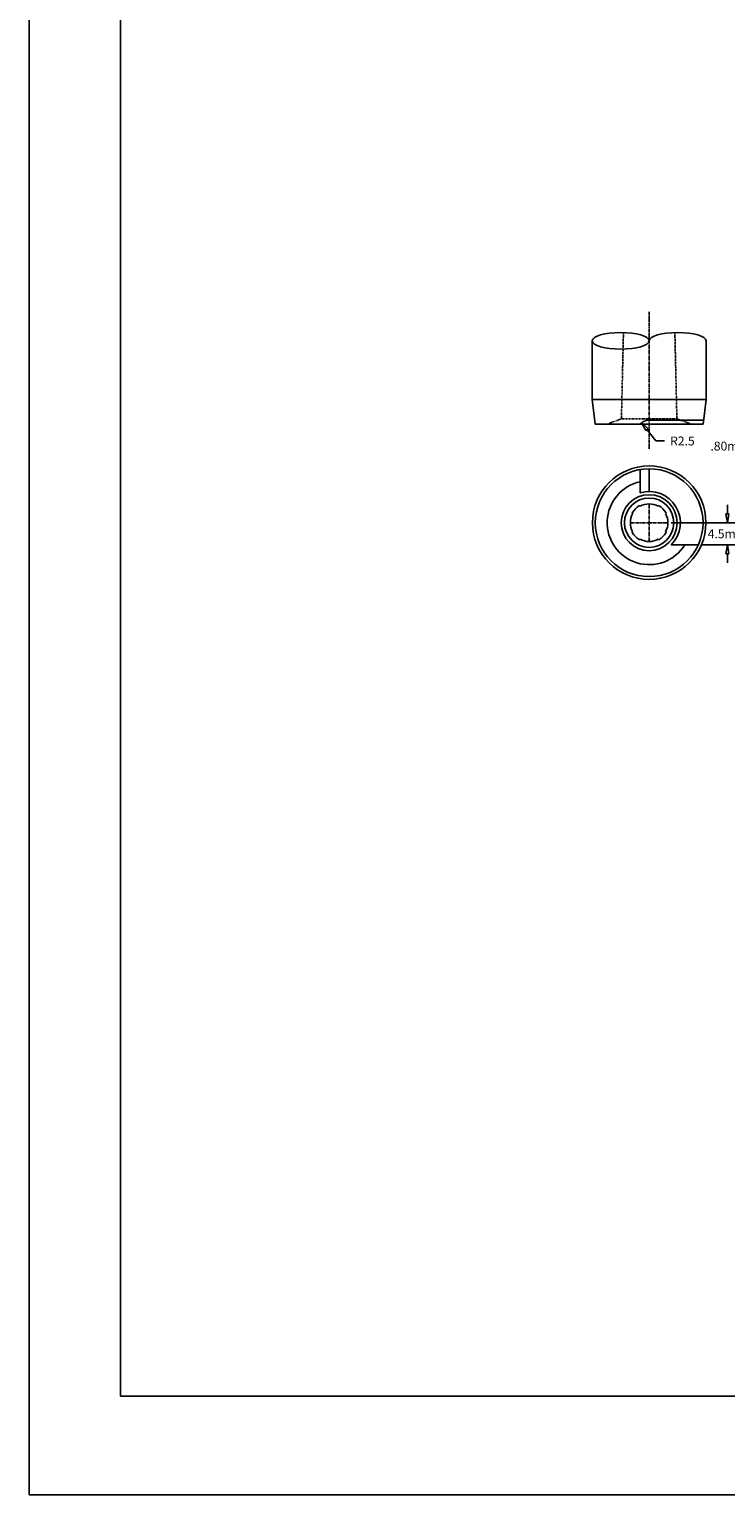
# Model space of a CAD drawing. Units: inches. Extents: x 0 to 841, y 0 to 594.
# Drawn here: x 0 to 141, y 0 to 297 of the extents above; entities that cross this region are included whole.
import ezdxf

# ---------------------------------------------------------------- set-up
doc = ezdxf.new("R2010")
doc.units = ezdxf.units.IN
doc.header["$MEASUREMENT"] = 0
doc.linetypes.add('CENTER2', pattern=[1.125, 0.75, -0.125, 0.125, -0.125])
doc.linetypes.add('HIDDEN2', pattern=[0.1875, 0.125, -0.0625])
doc.layers.add('CENTERLINE', color=1, linetype='CENTER2')
doc.layers.add('HIDDEN', color=5, linetype='HIDDEN2')
doc.dimstyles.get("Standard").update_dxf_attribs({"dimscale": 10, "dimtxt": 0.18, "dimasz": 0.18, "dimexe": 0.18, "dimexo": 0.0625, "dimgap": 0.09, "dimtad": 0, "dimtih": 1, "dimtoh": 1, "dimdec": 4, "dimzin": 0, "dimdsep": 46, "dimtxsty": 'Standard', "dimblk": 'CLOSEDBLANK', "dimcen": 0.09, "dimadec": 4, "dimazin": 0, "dimtfac": 1, "dimtdec": 4, "dimtofl": 0, "dimtmove": 0, "dimatfit": 3, "dimldrblk": 'CLOSEDBLANK', "dimfxl": 0, "dimtolj": 1, "dimtzin": 0, "dimarcsym": 0})
doc.dimstyles.new('Standard$0', dxfattribs={"dimscale": 10, "dimtxt": 0.18, "dimasz": 0.18, "dimexe": 0.18, "dimexo": 0.0625, "dimgap": 0.09, "dimtad": 0, "dimtih": 1, "dimtoh": 1, "dimdec": 4, "dimzin": 4, "dimdsep": 46, "dimtxsty": 'Standard', "dimblk": 'CLOSEDBLANK', "dimcen": 0.09, "dimadec": 5, "dimazin": 1, "dimtfac": 1, "dimtdec": 4, "dimtofl": 0, "dimtmove": 0, "dimatfit": 3, "dimldrblk": 'CLOSEDBLANK', "dimfxl": 0, "dimtolj": 1, "dimtzin": 0, "dimarcsym": 0})

# ---------------------------------------------------------------- blocks, each defined once
blk = doc.blocks.new('_ClosedBlank')
at = {"color": 0, "linetype": 'ByBlock', "lineweight": -2}
for p, q in [((-1, 0.17), (0, 0)), ((-1, 0.17), (-1, -0.17)), ((0, 0), (-1, -0.17))]:
    blk.add_line(p, q, dxfattribs=at)
blk = doc.blocks.new('*D7')
at = {"color": 0, "lineweight": -2}
for p, q in [((150, 208.55), (150, 214.33)), ((150.8, 208.43), (150.8, 214.33)), ((148.2, 212.53), (146.4, 212.53)), ((152.6, 212.53), (154.4, 212.53))]:
    blk.add_line(p, q, dxfattribs=at)
at = {"layer": 'Defpoints', "color": 0}
for p in [(150.8, 212.53), (150, 207.92), (150.8, 207.8)]:
    blk.add_point(p, dxfattribs=at)
at = {"color": 0, "lineweight": -2, "xscale": 1.8, "yscale": 1.8, "zscale": 1.8}
blk.add_blockref('_ClosedBlank', (150, 212.53), dxfattribs=at)
at = {"color": 0, "lineweight": -2, "xscale": 1.8, "yscale": 1.8, "zscale": 1.8, "rotation": 180}
blk.add_blockref('_ClosedBlank', (150.8, 212.53), dxfattribs=at)
at = {"color": 0, "insert": (142.05, 212.53), "char_height": 1.8, "attachment_point": 5}
blk.add_mtext('\\A1;.80mm', dxfattribs=at)
blk = doc.blocks.new('*D24')
at = {"color": 0, "lineweight": -2}
for p, q in [((141.5, 198.8), (141.5, 200.6)), ((130.08, 197), (143.3, 197)), ((136.23, 192.5), (143.3, 192.5)), ((141.5, 190.7), (141.5, 188.9))]:
    blk.add_line(p, q, dxfattribs=at)
at = {"layer": 'Defpoints', "color": 0}
for p in [(129.46, 197), (141.5, 197), (135.6, 192.5)]:
    blk.add_point(p, dxfattribs=at)
at = {"color": 0, "lineweight": -2, "xscale": 1.8, "yscale": 1.8, "zscale": 1.8}
for p, rotation in [((141.5, 197), 270), ((141.5, 192.5), 90)]:
    blk.add_blockref('_ClosedBlank', p, dxfattribs=dict(at, rotation=rotation))
at = {"color": 0, "insert": (141.5, 194.75), "char_height": 1.8, "attachment_point": 5}
blk.add_mtext('\\A1;4.5mm', dxfattribs=at)
blk = doc.blocks.new('*D25')
at = {"color": 0, "lineweight": -2}
for p, q in [((126.99, 213.56), (125.22, 215.85)), ((128.79, 213.56), (126.99, 213.56))]:
    blk.add_line(p, q, dxfattribs=at)
at = {"layer": 'Defpoints', "color": 0}
for p in [(124.12, 217.28), (125.65, 215.3)]:
    blk.add_point(p, dxfattribs=at)
at = {"color": 0, "lineweight": -2, "xscale": 1.8, "yscale": 1.8, "zscale": 1.8, "rotation": 127.7379653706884}
blk.add_blockref('_ClosedBlank', (124.12, 217.28), dxfattribs=at)
at = {"color": 0, "insert": (132.39, 213.56), "char_height": 1.8, "attachment_point": 5}
blk.add_mtext('\\A1;R2.5', dxfattribs=at)

msp = doc.modelspace()

# ---------------------------------------------------------------- linework, layer by layer
for p, q in [((114.11496, 222.00003), (114.11496, 233.86689)), ((137.18496, 222.00003), (137.18496, 233.86689)), ((137.18496, 222.00003), (114.11496, 222.00003)), ((114.72888, 217.00003), (114.11496, 222.00003)), ((136.57104, 217.00003), (137.18496, 222.00003)), ((136.57104, 217.00003), (114.72888, 217.00003)), ((136.66927, 217.80003), (125.64996, 217.80003)), ((125.64996, 203.33083), (125.64996, 207.92113)), ((123.81693, 203.05965), (123.81693, 207.7662)), ((130.10294, 192.50003), (135.60087, 192.50003))]:
    msp.add_line(p, q)
for points in [[(0, 0), (841, 0), (841, 594), (0, 594)], [(18.5, 20), (822.5, 20), (822.5, 574), (18.5, 574)]]:
    msp.add_lwpolyline(points, close=True)
for radius in [11.5, 10.9211, 5.67115, 5]:
    msp.add_circle((125.64996, 197.00003), radius)
for centre, radius, start, end in [((125.64996, 215.30003), 2.5, 90, 137.156357), ((125.64996, 197.00003), 8.5, 102.4537006, 328.0342812), ((125.64996, 197.00003), 6.3308, 314.6990904, 106.8305173)]:
    msp.add_arc(centre, radius, start, end)
at = {"ltscale": 0.25}
for centre, radius, start, end in [((122.3825, 198.95957), 0.1524, 149.0482979, 240.1945192), ((125.64996, 197.00003), 3.9624, 120.9517021, 149.0482979), ((123.69042, 200.26749), 0.1524, 29.8054808, 120.9517021), ((125.64996, 197.00003), 3.81, 61.3407406, 118.6592594), ((127.6095, 200.26749), 0.1524, 59.0482979, 150.1945192), ((125.64996, 197.00003), 3.9624, 30.9517021, 59.0482979), ((128.91742, 198.95957), 0.1524, 299.8054808, 30.9517021), ((125.64996, 197.00003), 3.81, 151.3407406, 208.6592594), ((125.64996, 197.00003), 3.81, 331.3407406, 28.6592594), ((122.3825, 195.04049), 0.1524, 119.8054808, 210.9517021), ((125.64996, 197.00003), 3.9624, 210.9517021, 239.0482979), ((123.69042, 193.73257), 0.1524, 239.0482979, 330.1945192), ((125.64996, 197.00003), 3.81, 241.3407406, 298.6592594), ((127.6095, 193.73257), 0.1524, 209.8054808, 300.9517021), ((125.64996, 197.00003), 3.9624, 300.9517021, 329.0482979), ((128.91742, 195.04049), 0.1524, 329.0482979, 60.1945192)]:
    msp.add_arc(centre, radius, start, end, dxfattribs=at)
msp.add_ellipse((119.88246, 233.86689), major_axis=(-5.7675, 0), ratio=0.291449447)
msp.add_ellipse((131.41746, 233.86689), major_axis=(-5.7675, 0), ratio=0.291449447, start_param=3.141592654, end_param=6.283185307)
at = {"layer": 'CENTERLINE'}
for p, q in [((125.64996, 212.00003), (125.64996, 239.89728)), ((125.64996, 193.19003), (125.64996, 200.81003)), ((121.83996, 197.00003), (129.45996, 197.00003))]:
    msp.add_line(p, q, dxfattribs=at)
at = {"layer": 'HIDDEN'}
for p, q in [((120.02852, 218.02964), (120.43902, 235.53998)), ((131.2714, 218.02964), (130.8609, 235.53998)), ((119.97879, 218.02964), (117.14996, 217.00003)), ((131.32113, 218.02964), (119.97879, 218.02964)), ((131.32113, 218.02964), (134.14996, 217.00003))]:
    msp.add_line(p, q, dxfattribs=at)

# ---------------------------------------------------------------- dimensions: what is measured, and where the dimension line sits
dim = msp.add_radius_dim(center=(125.64996, 215.30003), mpoint=(124.11983, 217.27707), dimstyle='Standard', override={"dimdec": 1, "dimtmove": 1})
dim.commit()
dim.dimension.update_dxf_attribs({"geometry": '*D25', "text_midpoint": (126.99376, 213.56374), "dimtype": 164})
dim = msp.add_linear_dim(base=(150.79996, 212.52503), p1=(149.99996, 207.92111), p2=(150.79996, 207.80329), dimstyle='Standard$0', override={"dimscale": 10, "dimdec": 2, "dimpost": 'mm', "dimblk1": 'ClosedBlank', "dimblk2": 'ClosedBlank', "dimsah": 1})
dim.commit()
dim.dimension.update_dxf_attribs({"geometry": '*D7', "text_midpoint": (142.04996, 212.52503), "dimtype": 160})
dim = msp.add_linear_dim(base=(141.49721, 197.00003), p1=(135.60087, 192.50003), p2=(129.45996, 197.00003), angle=90, dimstyle='Standard$0', override={"dimdec": 1, "dimpost": 'mm'})
dim.commit()
dim.dimension.update_dxf_attribs({"geometry": '*D24', "text_midpoint": (141.49721, 194.75003)})

doc.saveas('drawing.dxf')
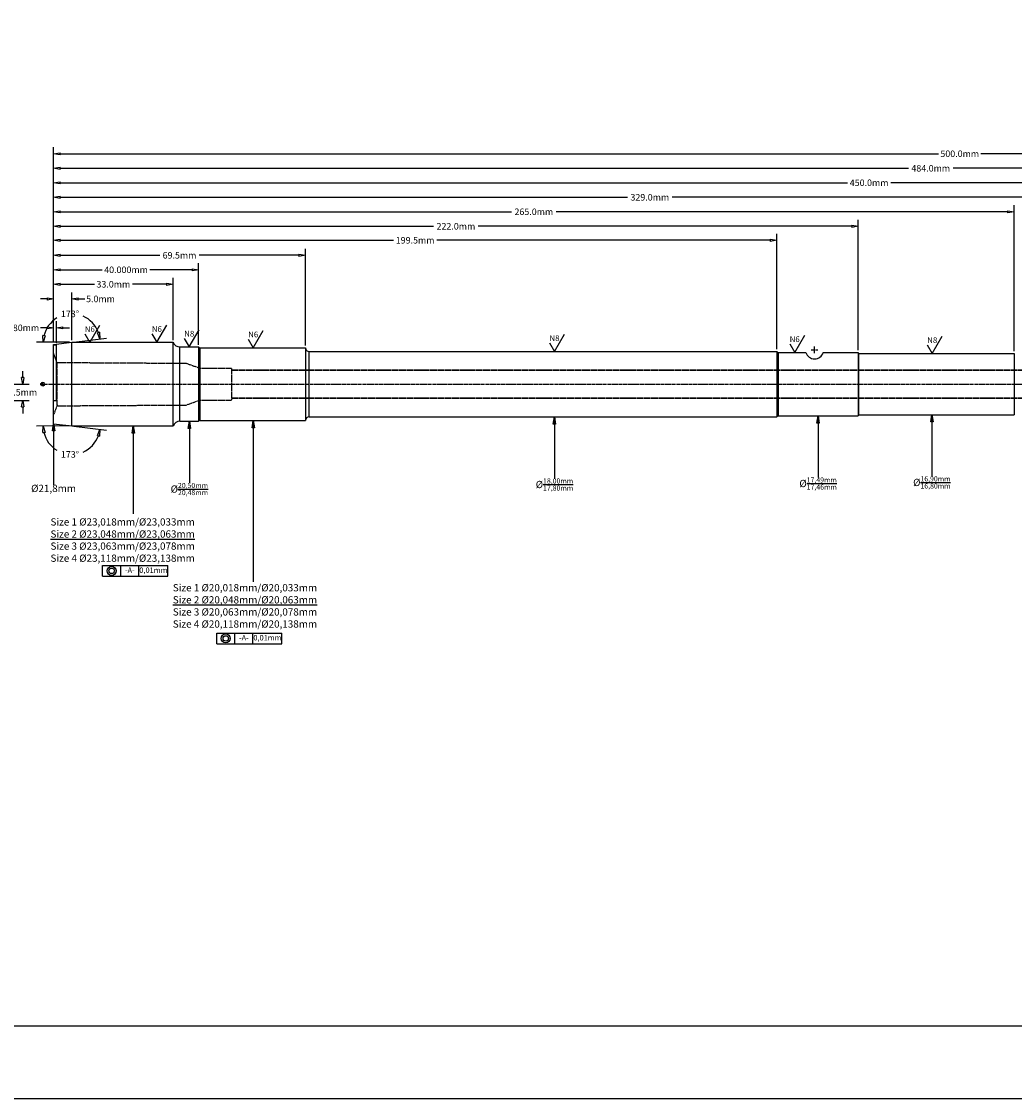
# Model space of a CAD drawing. Units: inches. Extents: x 0 to 841, y 0 to 594.
# Drawn here: x 141 to 415, y 0 to 297 of the extents above; entities that cross this region are included whole.
import ezdxf
from ezdxf.enums import TextEntityAlignment as Align

# ---------------------------------------------------------------- set-up
doc = ezdxf.new("R2010")
doc.units = ezdxf.units.IN
doc.header["$MEASUREMENT"] = 0
doc.linetypes.add('CENTER2', pattern=[1.125, 0.75, -0.125, 0.125, -0.125])
doc.linetypes.add('HIDDEN2', pattern=[0.1875, 0.125, -0.0625])
for name, color, linetype in [('CENTER', 1, 'CENTER2'), ('CENTERLINE', 1, 'CENTER2'), ('HIDDEN', 5, 'HIDDEN2'), ('TEXT', 5, 'Continuous')]:
    doc.layers.add(name, color=color, linetype=linetype)
doc.dimstyles.get("Standard").update_dxf_attribs({"dimscale": 10, "dimtxt": 0.18, "dimasz": 0.18, "dimexe": 0.18, "dimexo": 0.0625, "dimgap": 0.09, "dimtad": 0, "dimtih": 1, "dimtoh": 1, "dimdec": 4, "dimzin": 0, "dimdsep": 46, "dimtxsty": 'Standard', "dimblk": 'CLOSEDBLANK', "dimcen": 0.09, "dimadec": 4, "dimazin": 0, "dimtfac": 1, "dimtdec": 4, "dimtofl": 0, "dimtmove": 0, "dimatfit": 3, "dimldrblk": 'CLOSEDBLANK', "dimfxl": 0, "dimtolj": 1, "dimtzin": 0, "dimarcsym": 0})
doc.dimstyles.new('Standard$0', dxfattribs={"dimscale": 10, "dimtxt": 0.18, "dimasz": 0.18, "dimexe": 0.18, "dimexo": 0.0625, "dimgap": 0.09, "dimtad": 0, "dimtih": 1, "dimtoh": 1, "dimdec": 4, "dimzin": 4, "dimdsep": 46, "dimtxsty": 'Standard', "dimblk": 'CLOSEDBLANK', "dimcen": 0.09, "dimadec": 5, "dimazin": 1, "dimtfac": 1, "dimtdec": 4, "dimtofl": 0, "dimtmove": 0, "dimatfit": 3, "dimldrblk": 'CLOSEDBLANK', "dimfxl": 0, "dimtolj": 1, "dimtzin": 0, "dimarcsym": 0})

# ---------------------------------------------------------------- blocks, each defined once
blk = doc.blocks.new('_ClosedBlank')
at = {"color": 0, "linetype": 'ByBlock', "lineweight": -2}
for p, q in [((-1, 0.17), (0, 0)), ((-1, 0.17), (-1, -0.17)), ((0, 0), (-1, -0.17))]:
    blk.add_line(p, q, dxfattribs=at)
blk = doc.blocks.new('*D7')
at = {"color": 0, "lineweight": -2}
for p, q in [((150, 208.55), (150, 214.33)), ((150.8, 208.43), (150.8, 214.33)), ((148.2, 212.53), (146.4, 212.53)), ((152.6, 212.53), (154.4, 212.53))]:
    blk.add_line(p, q, dxfattribs=at)
at = {"layer": 'Defpoints', "color": 0}
for p in [(150.8, 212.53), (150, 207.92), (150.8, 207.8)]:
    blk.add_point(p, dxfattribs=at)
at = {"color": 0, "lineweight": -2, "xscale": 1.8, "yscale": 1.8, "zscale": 1.8}
blk.add_blockref('_ClosedBlank', (150, 212.53), dxfattribs=at)
at = {"color": 0, "lineweight": -2, "xscale": 1.8, "yscale": 1.8, "zscale": 1.8, "rotation": 180}
blk.add_blockref('_ClosedBlank', (150.8, 212.53), dxfattribs=at)
at = {"color": 0, "insert": (142.05, 212.53), "char_height": 1.8, "attachment_point": 5}
blk.add_mtext('\\A1;.80mm', dxfattribs=at)
blk = doc.blocks.new('*D8')
at = {"color": 0, "lineweight": -2}
for p, q in [((148.2, 220.5), (146.4, 220.5)), ((150, 208.55), (150, 222.3)), ((155, 209.16), (155, 222.3)), ((156.8, 220.5), (158.6, 220.5))]:
    blk.add_line(p, q, dxfattribs=at)
at = {"layer": 'Defpoints', "color": 0}
for p in [(155, 220.5), (150, 207.92), (155, 208.54)]:
    blk.add_point(p, dxfattribs=at)
at = {"color": 0, "lineweight": -2, "xscale": 1.8, "yscale": 1.8, "zscale": 1.8}
blk.add_blockref('_ClosedBlank', (150, 220.5), dxfattribs=at)
at = {"color": 0, "lineweight": -2, "xscale": 1.8, "yscale": 1.8, "zscale": 1.8, "rotation": 180}
blk.add_blockref('_ClosedBlank', (155, 220.5), dxfattribs=at)
at = {"color": 0, "insert": (162.95, 220.5), "char_height": 1.8, "attachment_point": 5}
blk.add_mtext('\\A1;5.0mm', dxfattribs=at)
blk = doc.blocks.new('*D9')
at = {"color": 0, "lineweight": -2}
for p, q in [((150, 208.55), (150, 226.34)), ((183, 209.16), (183, 226.34)), ((151.8, 224.54), (161.25, 224.54)), ((181.2, 224.54), (171.75, 224.54))]:
    blk.add_line(p, q, dxfattribs=at)
at = {"layer": 'Defpoints', "color": 0}
for p in [(183, 224.54), (150, 207.92), (183, 208.54)]:
    blk.add_point(p, dxfattribs=at)
at = {"color": 0, "lineweight": -2, "xscale": 1.8, "yscale": 1.8, "zscale": 1.8, "rotation": 180}
blk.add_blockref('_ClosedBlank', (150, 224.54), dxfattribs=at)
at = {"color": 0, "lineweight": -2, "xscale": 1.8, "yscale": 1.8, "zscale": 1.8}
blk.add_blockref('_ClosedBlank', (183, 224.54), dxfattribs=at)
at = {"color": 0, "insert": (166.5, 224.54), "char_height": 1.8, "attachment_point": 5}
blk.add_mtext('\\A1;33.0mm', dxfattribs=at)
blk = doc.blocks.new('*D10')
at = {"color": 0, "lineweight": -2}
for p, q in [((150, 208.55), (150, 230.33)), ((190, 207.88), (190, 230.33)), ((151.8, 228.53), (163.4, 228.53)), ((188.2, 228.53), (176.6, 228.53))]:
    blk.add_line(p, q, dxfattribs=at)
at = {"layer": 'Defpoints', "color": 0}
for p in [(150, 228.53), (150, 207.92), (190, 207.25)]:
    blk.add_point(p, dxfattribs=at)
at = {"color": 0, "lineweight": -2, "xscale": 1.8, "yscale": 1.8, "zscale": 1.8, "rotation": 180}
blk.add_blockref('_ClosedBlank', (150, 228.53), dxfattribs=at)
at = {"color": 0, "lineweight": -2, "xscale": 1.8, "yscale": 1.8, "zscale": 1.8}
blk.add_blockref('_ClosedBlank', (190, 228.53), dxfattribs=at)
at = {"color": 0, "insert": (170, 228.53), "char_height": 1.8, "attachment_point": 5}
blk.add_mtext('\\A1;40.000mm', dxfattribs=at)
blk = doc.blocks.new('*D11')
at = {"color": 0, "lineweight": -2}
for p, q in [((150, 208.55), (150, 234.33)), ((151.8, 232.53), (179.35, 232.53)), ((217.7, 232.53), (190.15, 232.53)), ((219.5, 207.65), (219.5, 234.33))]:
    blk.add_line(p, q, dxfattribs=at)
at = {"layer": 'Defpoints', "color": 0}
for p in [(150, 232.53), (150, 207.92), (219.5, 207.03)]:
    blk.add_point(p, dxfattribs=at)
at = {"color": 0, "lineweight": -2, "xscale": 1.8, "yscale": 1.8, "zscale": 1.8, "rotation": 180}
blk.add_blockref('_ClosedBlank', (150, 232.53), dxfattribs=at)
at = {"color": 0, "lineweight": -2, "xscale": 1.8, "yscale": 1.8, "zscale": 1.8}
blk.add_blockref('_ClosedBlank', (219.5, 232.53), dxfattribs=at)
at = {"color": 0, "insert": (184.75, 232.53), "char_height": 1.8, "attachment_point": 5}
blk.add_mtext('\\A1;69.5mm', dxfattribs=at)
blk = doc.blocks.new('*D12')
at = {"color": 0, "lineweight": -2}
for p, q in [((150, 208.55), (150, 238.48)), ((349.5, 206.63), (349.5, 238.48)), ((151.8, 236.68), (243.75, 236.68)), ((347.7, 236.68), (255.75, 236.68))]:
    blk.add_line(p, q, dxfattribs=at)
at = {"layer": 'Defpoints', "color": 0}
for p in [(150, 236.68), (150, 207.92), (349.5, 206)]:
    blk.add_point(p, dxfattribs=at)
at = {"color": 0, "lineweight": -2, "xscale": 1.8, "yscale": 1.8, "zscale": 1.8, "rotation": 180}
blk.add_blockref('_ClosedBlank', (150, 236.68), dxfattribs=at)
at = {"color": 0, "lineweight": -2, "xscale": 1.8, "yscale": 1.8, "zscale": 1.8}
blk.add_blockref('_ClosedBlank', (349.5, 236.68), dxfattribs=at)
at = {"color": 0, "insert": (249.75, 236.68), "char_height": 1.8, "attachment_point": 5}
blk.add_mtext('\\A1;199.5mm', dxfattribs=at)
blk = doc.blocks.new('*D13')
at = {"color": 0, "lineweight": -2}
for p, q in [((150, 208.55), (150, 242.33)), ((372, 206.35), (372, 242.33)), ((151.8, 240.53), (254.85, 240.53)), ((370.2, 240.53), (267.15, 240.53))]:
    blk.add_line(p, q, dxfattribs=at)
at = {"layer": 'Defpoints', "color": 0}
for p in [(150, 240.53), (150, 207.92), (372, 205.73)]:
    blk.add_point(p, dxfattribs=at)
at = {"color": 0, "lineweight": -2, "xscale": 1.8, "yscale": 1.8, "zscale": 1.8, "rotation": 180}
blk.add_blockref('_ClosedBlank', (150, 240.53), dxfattribs=at)
at = {"color": 0, "lineweight": -2, "xscale": 1.8, "yscale": 1.8, "zscale": 1.8}
blk.add_blockref('_ClosedBlank', (372, 240.53), dxfattribs=at)
at = {"color": 0, "insert": (261, 240.53), "char_height": 1.8, "attachment_point": 5}
blk.add_mtext('\\A1;222.0mm', dxfattribs=at)
blk = doc.blocks.new('*D14')
at = {"color": 0, "lineweight": -2}
for p, q in [((150, 208.55), (150, 246.33)), ((151.8, 244.53), (276.35, 244.53)), ((413.2, 244.53), (288.65, 244.53)), ((415, 206.08), (415, 246.33))]:
    blk.add_line(p, q, dxfattribs=at)
at = {"layer": 'Defpoints', "color": 0}
for p in [(150, 244.53), (150, 207.92), (415, 205.45)]:
    blk.add_point(p, dxfattribs=at)
at = {"color": 0, "lineweight": -2, "xscale": 1.8, "yscale": 1.8, "zscale": 1.8, "rotation": 180}
blk.add_blockref('_ClosedBlank', (150, 244.53), dxfattribs=at)
at = {"color": 0, "lineweight": -2, "xscale": 1.8, "yscale": 1.8, "zscale": 1.8}
blk.add_blockref('_ClosedBlank', (415, 244.53), dxfattribs=at)
at = {"color": 0, "insert": (282.5, 244.53), "char_height": 1.8, "attachment_point": 5}
blk.add_mtext('\\A1;265.0mm', dxfattribs=at)
blk = doc.blocks.new('*D15')
at = {"color": 0, "lineweight": -2}
for p, q in [((150, 208.55), (150, 250.33)), ((479, 205.65), (479, 250.33)), ((151.8, 248.53), (308.35, 248.53)), ((477.2, 248.53), (320.65, 248.53))]:
    blk.add_line(p, q, dxfattribs=at)
at = {"layer": 'Defpoints', "color": 0}
for p in [(150, 248.53), (150, 207.92), (479, 205.03)]:
    blk.add_point(p, dxfattribs=at)
at = {"color": 0, "lineweight": -2, "xscale": 1.8, "yscale": 1.8, "zscale": 1.8, "rotation": 180}
blk.add_blockref('_ClosedBlank', (150, 248.53), dxfattribs=at)
at = {"color": 0, "lineweight": -2, "xscale": 1.8, "yscale": 1.8, "zscale": 1.8}
blk.add_blockref('_ClosedBlank', (479, 248.53), dxfattribs=at)
at = {"color": 0, "insert": (314.5, 248.53), "char_height": 1.8, "attachment_point": 5}
blk.add_mtext('\\A1;329.0mm', dxfattribs=at)
blk = doc.blocks.new('*D16')
at = {"color": 0, "lineweight": -2}
for p, q in [((150, 208.55), (150, 254.33)), ((151.8, 252.53), (369, 252.53)), ((598.2, 252.53), (381, 252.53)), ((600, 205.38), (600, 254.33))]:
    blk.add_line(p, q, dxfattribs=at)
at = {"layer": 'Defpoints', "color": 0}
for p in [(150, 252.53), (150, 207.92), (600, 204.75)]:
    blk.add_point(p, dxfattribs=at)
at = {"color": 0, "lineweight": -2, "xscale": 1.8, "yscale": 1.8, "zscale": 1.8, "rotation": 180}
blk.add_blockref('_ClosedBlank', (150, 252.53), dxfattribs=at)
at = {"color": 0, "lineweight": -2, "xscale": 1.8, "yscale": 1.8, "zscale": 1.8}
blk.add_blockref('_ClosedBlank', (600, 252.53), dxfattribs=at)
at = {"color": 0, "insert": (375, 252.53), "char_height": 1.8, "attachment_point": 5}
blk.add_mtext('\\A1;450.0mm', dxfattribs=at)
blk = doc.blocks.new('*D17')
at = {"color": 0, "lineweight": -2}
for p, q in [((150, 208.55), (150, 258.33)), ((151.8, 256.53), (385.85, 256.53)), ((632.2, 256.53), (398.15, 256.53)), ((634, 204.15), (634, 258.33))]:
    blk.add_line(p, q, dxfattribs=at)
at = {"layer": 'Defpoints', "color": 0}
for p in [(150, 256.53), (150, 207.92), (634, 203.53)]:
    blk.add_point(p, dxfattribs=at)
at = {"color": 0, "lineweight": -2, "xscale": 1.8, "yscale": 1.8, "zscale": 1.8, "rotation": 180}
blk.add_blockref('_ClosedBlank', (150, 256.53), dxfattribs=at)
at = {"color": 0, "lineweight": -2, "xscale": 1.8, "yscale": 1.8, "zscale": 1.8}
blk.add_blockref('_ClosedBlank', (634, 256.53), dxfattribs=at)
at = {"color": 0, "insert": (392, 256.53), "char_height": 1.8, "attachment_point": 5}
blk.add_mtext('\\A1;484.0mm', dxfattribs=at)
blk = doc.blocks.new('*D18')
at = {"color": 0, "lineweight": -2}
for p, q in [((150, 208.55), (150, 262.33)), ((650, 204.52), (650, 262.33)), ((151.8, 260.53), (394.15, 260.53)), ((648.2, 260.53), (405.85, 260.53))]:
    blk.add_line(p, q, dxfattribs=at)
at = {"layer": 'Defpoints', "color": 0}
for p in [(650, 260.53), (150, 207.92), (650, 203.89)]:
    blk.add_point(p, dxfattribs=at)
at = {"color": 0, "lineweight": -2, "xscale": 1.8, "yscale": 1.8, "zscale": 1.8, "rotation": 180}
blk.add_blockref('_ClosedBlank', (150, 260.53), dxfattribs=at)
at = {"color": 0, "lineweight": -2, "xscale": 1.8, "yscale": 1.8, "zscale": 1.8}
blk.add_blockref('_ClosedBlank', (650, 260.53), dxfattribs=at)
at = {"color": 0, "insert": (400, 260.53), "char_height": 1.8, "attachment_point": 5}
blk.add_mtext('\\A1;500.0mm', dxfattribs=at)
blk = doc.blocks.new('*D23')
at = {"color": 0, "lineweight": -2}
for p, q in [((154.37, 185.46), (145.34, 185.45)), ((155.62, 185.39), (164.59, 184.29))]:
    blk.add_line(p, q, dxfattribs=at)
for start, end in [(193.2527, 238.8041), (293.4369, 339.8547)]:
    blk.add_arc((155, 185.47), 7.86, start, end, dxfattribs=at)
at = {"layer": 'Defpoints', "color": 0}
for p in [(150, 186.08), (155, 185.47), (155, 185.47), (183, 185.52), (150.8, 178.82)]:
    blk.add_point(p, dxfattribs=at)
at = {"color": 0, "lineweight": -2, "xscale": 1.8, "yscale": 1.8, "zscale": 1.8}
for p, rotation in [((147.14, 185.45), 96.68008649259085), ((162.8, 184.51), 76.42734130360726)]:
    blk.add_blockref('_ClosedBlank', p, dxfattribs=dict(at, rotation=rotation))
at = {"color": 0, "insert": (154.53, 177.62), "char_height": 1.8, "attachment_point": 5}
blk.add_mtext('\\A1;173°', dxfattribs=at)
blk = doc.blocks.new('*D24')
at = {"color": 0, "lineweight": -2}
for p, q in [((141.5, 198.8), (141.5, 200.6)), ((130.08, 197), (143.3, 197)), ((136.23, 192.5), (143.3, 192.5)), ((141.5, 190.7), (141.5, 188.9))]:
    blk.add_line(p, q, dxfattribs=at)
at = {"layer": 'Defpoints', "color": 0}
for p in [(129.46, 197), (141.5, 197), (135.6, 192.5)]:
    blk.add_point(p, dxfattribs=at)
at = {"color": 0, "lineweight": -2, "xscale": 1.8, "yscale": 1.8, "zscale": 1.8}
for p, rotation in [((141.5, 197), 270), ((141.5, 192.5), 90)]:
    blk.add_blockref('_ClosedBlank', p, dxfattribs=dict(at, rotation=rotation))
at = {"color": 0, "insert": (141.5, 194.75), "char_height": 1.8, "attachment_point": 5}
blk.add_mtext('\\A1;4.5mm', dxfattribs=at)
blk = doc.blocks.new('*D26')
at = {"color": 0, "lineweight": -2}
for p, q in [((154.37, 208.54), (145.34, 208.55)), ((155.62, 208.61), (164.59, 209.71))]:
    blk.add_line(p, q, dxfattribs=at)
for start, end in [(121.1959, 166.7473), (20.1453, 66.5631)]:
    blk.add_arc((155, 208.54), 7.86, start, end, dxfattribs=at)
at = {"layer": 'Defpoints', "color": 0}
for p in [(158.37, 215.64), (150, 207.92), (155, 208.54), (155, 208.54), (183, 208.48)]:
    blk.add_point(p, dxfattribs=at)
at = {"color": 0, "lineweight": -2, "xscale": 1.8, "yscale": 1.8, "zscale": 1.8}
for p, rotation in [((162.8, 209.49), 283.5726586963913), ((147.14, 208.55), 263.3199135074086)]:
    blk.add_blockref('_ClosedBlank', p, dxfattribs=dict(at, rotation=rotation))
at = {"color": 0, "insert": (154.53, 216.38), "char_height": 1.8, "attachment_point": 5}
blk.add_mtext('\\A1;173°', dxfattribs=at)

msp = doc.modelspace()

# ---------------------------------------------------------------- hatches: boundary and pattern name
at = {"layer": 'CENTER'}
h = msp.add_hatch(dxfattribs=at)
h.set_pattern_fill('ANSI31', color=256, style=0)
h.set_pattern_definition([(45, (98, 147), (-0.08838835, 0.08838835), [])])
h.paths.add_polyline_path([(146.99996, 197.50003, 0.414213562), (146.49996, 197.00003), (146.99996, 197.00003)])
h.paths.add_polyline_path([(147.49996, 197.00003), (146.99996, 197.00003), (146.99996, 196.50003, 0.414213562)])

# ---------------------------------------------------------------- linework, layer by layer
for p, q in [((158.62514, 210.88128), (159.99996, 208.50003)), ((159.99996, 208.50003), (162.74959, 213.26253)), ((177.12514, 210.91628), (178.49996, 208.53503)), ((178.49996, 208.53503), (181.24959, 213.29753)), ((187.43408, 207.25003), (190.18371, 212.01253)), ((205.08396, 207.02503), (207.83359, 211.78753)), ((149.99996, 207.92111), (154.99996, 208.53503)), ((149.99996, 186.07895), (149.99996, 207.92111)), ((154.99996, 208.53503), (182.99996, 208.53503)), ((154.99996, 185.46503), (154.99996, 208.53503)), ((182.99996, 185.46503), (182.99996, 208.53503)), ((186.05927, 209.63128), (187.43408, 207.25003)), ((203.70914, 209.40628), (205.08396, 207.02503)), ((286.82106, 208.38128), (288.19588, 206.00003)), ((288.19588, 206.00003), (290.94551, 210.76253)), ((353.09681, 208.10628), (354.47163, 205.72503)), ((354.47163, 205.72503), (357.22126, 210.48753)), ((392.42545, 205.45003), (395.17508, 210.21253)), ((149.99996, 207.80329), (150.79996, 207.80329)), ((150.79996, 203.30205), (149.99996, 205.50003)), ((150.79996, 192.50003), (150.79996, 207.80329)), ((184.86779, 207.25003), (190.00038, 207.25003)), ((184.86779, 186.75003), (184.86779, 207.25003)), ((190.00038, 207.25003), (190.00038, 186.75003)), ((190.41796, 207.02503), (219.49996, 207.02503)), ((190.41796, 186.97503), (190.41796, 207.02503)), ((219.49996, 207.02503), (219.49996, 186.97503)), ((220.49996, 206.00003), (349.50001, 206.00003)), ((220.49996, 188.00003), (220.49996, 206.00003)), ((349.50001, 206.00003), (349.50001, 188.00003)), ((349.94396, 205.72503), (357.55049, 205.72503)), ((349.94396, 205.72503), (349.94396, 188.27503)), ((362.33743, 205.72503), (371.99996, 205.72503)), ((371.99996, 205.72503), (371.99996, 188.27503)), ((372.09996, 205.45003), (414.99996, 205.45003)), ((372.09996, 205.45003), (372.09996, 188.55003)), ((391.05063, 207.83128), (392.42545, 205.45003)), ((414.99996, 205.45003), (414.99996, 188.55003)), ((149.99996, 192.50003), (150.79996, 192.50003)), ((220.49996, 188.00003), (349.50001, 188.00003)), ((349.94396, 188.27503), (371.99996, 188.27503)), ((372.09996, 188.55003), (414.99996, 188.55003)), ((149.99996, 186.07895), (154.99996, 185.46503)), ((154.99996, 185.46503), (182.99996, 185.46503)), ((184.86779, 186.75003), (190.00038, 186.75003)), ((190.41796, 186.97503), (219.49996, 186.97503))]:
    msp.add_line(p, q)
for points in [[(0, 0), (841, 0), (841, 594), (0, 594)], [(18.5, 20), (822.5, 20), (822.5, 574), (18.5, 574)]]:
    msp.add_lwpolyline(points, close=True)
for centre, radius, start, end in [((184.86779, 209.25003), 2, 200.9467416, 270), ((190.41796, 207.52503), 0.5, 213.367013, 270), ((220.49996, 207.00003), 1, 180, 270), ((349.94652, 206.22502), 0.5, 206.7428404, 270), ((359.94396, 206.44703), 2.5, 196.7861274, 343.2138726), ((372.09996, 205.55003), 0.1, 180, 270), ((415.09996, 205.12503), 0.1, 180, 270), ((220.49996, 187.00003), 1, 90, 180), ((349.94396, 187.77503), 0.5, 90, 153.256316), ((372.09996, 188.45003), 0.1, 90, 180), ((415.09996, 188.87503), 0.1, 90, 180), ((184.86779, 184.75003), 2, 90, 159.0532584), ((190.41796, 186.47503), 0.5, 90, 146.632987)]:
    msp.add_arc(centre, radius, start, end)
for p, q in [((359.04396, 206.44703), (360.84396, 206.44703)), ((359.94396, 205.54703), (359.94396, 207.34703)), ((146.99996, 196.50003), (146.99996, 197.50003))]:
    msp.add_line(p, q, dxfattribs=at)
msp.add_circle((146.99996, 197.00003), 0.5, dxfattribs=at)
at = {"layer": 'CENTERLINE'}
msp.add_line((146.49996, 197.00003), (651.49996, 197.00003), dxfattribs=at)
at = {"layer": 'HIDDEN'}
for p, q in [((151.02957, 202.6712), (150.79996, 203.30205)), ((150.91879, 202.97556), (186.6124, 202.76507)), ((151.02957, 191.32886), (151.02957, 202.6712)), ((186.6124, 202.76507), (190.41796, 201.38601)), ((190.41796, 201.38601), (199.17996, 201.38601)), ((199.17996, 192.64003), (199.17996, 201.38601)), ((199.17996, 200.91003), (649.99996, 200.91003)), ((199.17996, 200.81003), (649.99996, 200.81003)), ((199.17996, 193.19003), (649.99996, 193.19003)), ((199.17996, 193.09003), (649.99996, 193.09003)), ((151.02957, 191.32886), (149.99996, 188.50003)), ((150.91879, 191.0245), (186.6124, 191.23498)), ((186.6124, 191.23498), (190.41796, 192.61405)), ((190.41796, 192.61405), (199.17996, 192.61405))]:
    msp.add_line(p, q, dxfattribs=at)
at = {"layer": 'TEXT', "color": 7}
for p, q in [((163.5396, 144), (163.5396, 147)), ((163.5396, 147), (168.5396, 147)), ((168.5396, 147), (173.5396, 147)), ((168.5396, 144), (168.5396, 147)), ((173.5396, 147), (181.5396, 147)), ((173.5396, 144), (173.5396, 147)), ((181.5396, 144), (181.5396, 147)), ((163.5396, 144), (168.5396, 144)), ((168.5396, 144), (173.5396, 144)), ((173.5396, 144), (181.5396, 144)), ((195.00824, 125.3672), (195.00824, 128.3672)), ((195.00824, 128.3672), (200.00824, 128.3672)), ((200.00824, 128.3672), (205.00824, 128.3672)), ((200.00824, 125.3672), (200.00824, 128.3672)), ((205.00824, 128.3672), (213.00824, 128.3672)), ((205.00824, 125.3672), (205.00824, 128.3672)), ((213.00824, 125.3672), (213.00824, 128.3672)), ((195.00824, 125.3672), (200.00824, 125.3672)), ((200.00824, 125.3672), (205.00824, 125.3672)), ((205.00824, 125.3672), (213.00824, 125.3672))]:
    msp.add_line(p, q, dxfattribs=at)
for centre, radius in [((166.0396, 145.5), 1.25), ((166.0396, 145.5), 0.75), ((197.50824, 126.8672), 1.25), ((197.50824, 126.8672), 0.75)]:
    msp.add_circle(centre, radius, dxfattribs=at)

# ---------------------------------------------------------------- texts
for s, p in [('N6', (159.99996, 210.88128)), ('N6', (178.49996, 210.91628)), ('N8', (187.43408, 209.63128)), ('N6', (205.08396, 209.40628)), ('N8', (288.19588, 208.38128)), ('N6', (354.47163, 208.10628)), ('N8', (392.42545, 207.83128))]:
    msp.add_text(s, height=1.5875).set_placement(p, align=Align.BOTTOM_CENTER)
at = {"char_height": 2, "width": 10.5482646, "attachment_point": 2}
for s, insert in [('\\A1;%%C21,8mm', (149.99996, 169.24774)), ('\\A1;%%C{\\H0.7x;\\S20,50mm/20,48mm;}', (187.46271, 169.75003)), ('\\A1;%%C{\\H0.7x;\\S18,00mm/17,80mm;}', (288.1946, 171.00003)), ('\\A1;%%C{\\H0.7x;\\S17,49mm/17,46mm;}', (360.92196, 171.27503)), ('\\A1;%%C{\\H0.7x;\\S16,90mm/16,80mm;}', (392.30998, 171.57003))]:
    msp.add_mtext(s, dxfattribs=dict(at, insert=insert))
at = {"layer": 'TEXT', "color": 7}
for s, insert, char_height, width, attachment_point in [('\\A1;Size 1 %%C23,018mm/%%C23,033mm\\P{\\LSize 2 %%C23,048mm/%%C23,063mm}\\PSize 3 %%C23,063mm/%%C23,078mm\\PSize 4 %%C23,118mm/%%C23,138mm', (149.15454, 160), 2, 48.5376086, 1), ('-A-', (171.0396, 145.5), 1.5, 1.19634, 5), ('0,01mm', (177.5396, 145.5), 1.5, 6.6720954, 5), ('\\A1;Size 1 %%C20,018mm/%%C20,033mm\\P{\\LSize 2 %%C20,048mm/%%C20,063mm}\\PSize 3 %%C20,063mm/%%C20,078mm\\PSize 4 %%C20,118mm/%%C20,138mm', (182.90039, 141.85018), 2, 48.5376086, 1), ('-A-', (202.50824, 126.8672), 1.5, 1.19634, 5), ('0,01mm', (209.00824, 126.8672), 1.5, 6.6720954, 5)]:
    msp.add_mtext(s, dxfattribs=dict(at, insert=insert, char_height=char_height, width=width, attachment_point=attachment_point))

# ---------------------------------------------------------------- dimensions: what is measured, and where the dimension line sits
for base, p1, p2, override, picture, middle in [((649.99996, 260.52503), (149.99996, 207.92111), (649.99996, 203.89178), {"dimscale": 10, "dimdec": 1, "dimpost": 'mm', "dimblk1": 'ClosedBlank', "dimblk2": 'ClosedBlank', "dimsah": 1}, '*D18', (399.99996, 260.52503)), ((149.99996, 256.52503), (633.99996, 203.52503), (149.99996, 207.92111), {"dimscale": 10, "dimdec": 1, "dimpost": 'mm', "dimblk1": 'ClosedBlank', "dimblk2": 'ClosedBlank', "dimsah": 1}, '*D17', (391.99996, 256.52503)), ((149.99996, 252.52503), (599.99996, 204.75003), (149.99996, 207.92111), {"dimscale": 10, "dimdec": 1, "dimpost": 'mm', "dimblk1": 'ClosedBlank', "dimblk2": 'ClosedBlank', "dimsah": 1}, '*D16', (374.99996, 252.52503)), ((149.99996, 248.52503), (478.99996, 205.02503), (149.99996, 207.92111), {"dimscale": 10, "dimdec": 1, "dimpost": 'mm', "dimblk1": 'ClosedBlank', "dimblk2": 'ClosedBlank', "dimsah": 1}, '*D15', (314.49996, 248.52503)), ((149.99996, 244.52503), (414.99996, 205.45003), (149.99996, 207.92111), {"dimscale": 10, "dimdec": 1, "dimpost": 'mm', "dimblk1": 'ClosedBlank', "dimblk2": 'ClosedBlank', "dimsah": 1}, '*D14', (282.49996, 244.52503)), ((149.99996, 240.52503), (371.99996, 205.72503), (149.99996, 207.92111), {"dimscale": 10, "dimdec": 1, "dimpost": 'mm', "dimblk1": 'ClosedBlank', "dimblk2": 'ClosedBlank', "dimsah": 1}, '*D13', (260.99996, 240.52503)), ((149.99996, 236.67503), (349.50001, 206.00003), (149.99996, 207.92111), {"dimscale": 10, "dimdec": 1, "dimpost": 'mm', "dimblk1": 'ClosedBlank', "dimblk2": 'ClosedBlank', "dimsah": 1}, '*D12', (249.74998, 236.67503)), ((149.99996, 232.52503), (219.49996, 207.02503), (149.99996, 207.92111), {"dimscale": 10, "dimdec": 1, "dimpost": 'mm', "dimblk1": 'ClosedBlank', "dimblk2": 'ClosedBlank', "dimsah": 1}, '*D11', (184.74996, 232.52503)), ((149.99996, 228.52503), (190.00038, 207.25003), (149.99996, 207.92111), {"dimdec": 3, "dimpost": 'mm', "dimblk1": 'ClosedBlank', "dimblk2": 'ClosedBlank', "dimsah": 1}, '*D10', (170.00017, 228.52503)), ((182.99996, 224.53503), (149.99996, 207.92111), (182.99996, 208.53503), {"dimscale": 10, "dimdec": 1, "dimpost": 'mm', "dimblk1": 'ClosedBlank', "dimblk2": 'ClosedBlank', "dimsah": 1}, '*D9', (166.49996, 224.53503)), ((154.99996, 220.50003), (149.99996, 207.92111), (154.99996, 208.53503), {"dimscale": 10, "dimdec": 1, "dimpost": 'mm', "dimblk1": 'ClosedBlank', "dimblk2": 'ClosedBlank', "dimsah": 1}, '*D8', (162.94996, 220.50003))]:
    dim = msp.add_linear_dim(base=base, p1=p1, p2=p2, dimstyle='Standard$0', override=override)
    dim.commit()
    dim.dimension.update_dxf_attribs({"geometry": picture, "text_midpoint": middle})
for base, line1, line2, picture, middle in [((158.36876, 215.63959), ((154.99996, 208.53503), (183.00004, 208.48253)), ((149.99996, 207.92111), (154.99996, 208.53503)), '*D26', (154.52731, 216.38361)), ((150.8029, 178.8161), ((154.99996, 185.46503), (183.00004, 185.51753)), ((149.99996, 186.07895), (154.99996, 185.46503)), '*D23', (154.52731, 177.61645))]:
    dim = msp.add_angular_dim_2l(base=base, line1=line1, line2=line2, dimstyle='Standard', override={"dimadec": 0})
    dim.commit()
    dim.dimension.update_dxf_attribs({"geometry": picture, "text_midpoint": middle})
dim = msp.add_linear_dim(base=(150.79996, 212.52503), p1=(149.99996, 207.92111), p2=(150.79996, 207.80329), dimstyle='Standard$0', override={"dimscale": 10, "dimdec": 2, "dimpost": 'mm', "dimblk1": 'ClosedBlank', "dimblk2": 'ClosedBlank', "dimsah": 1})
dim.commit()
dim.dimension.update_dxf_attribs({"geometry": '*D7', "text_midpoint": (142.04996, 212.52503), "dimtype": 160})
dim = msp.add_linear_dim(base=(141.49721, 197.00003), p1=(135.60087, 192.50003), p2=(129.45996, 197.00003), angle=90, dimstyle='Standard$0', override={"dimdec": 1, "dimpost": 'mm'})
dim.commit()
dim.dimension.update_dxf_attribs({"geometry": '*D24', "text_midpoint": (141.49721, 194.75003)})

# ---------------------------------------------------------------- leaders
for points in [[(288.1946, 188.00003), (288.1946, 171.00003)], [(360.92196, 188.27503), (360.92196, 171.27503)], [(392.30998, 188.57003), (392.30998, 171.57003)], [(149.99996, 186.07895), (149.99996, 169.24774)], [(187.46271, 186.75003), (187.46271, 169.75003)]]:
    msp.add_leader(points, dimstyle='Standard', override={"dimscale": 1, "dimasz": 2, "dimgap": 0.09, "dimtad": 0, "dimldrblk": 'ClosedBlank'})
for points in [[(171.99996, 185.46503), (171.99996, 161.23901)], [(205.08396, 186.97503), (205.08396, 142.45279)]]:
    msp.add_leader(points, dimstyle='Standard', override={"dimscale": 1, "dimasz": 2, "dimgap": 0.09, "dimtad": 0, "dimldrblk": 'ClosedBlank'}, dxfattribs=at)

doc.saveas('drawing.dxf')
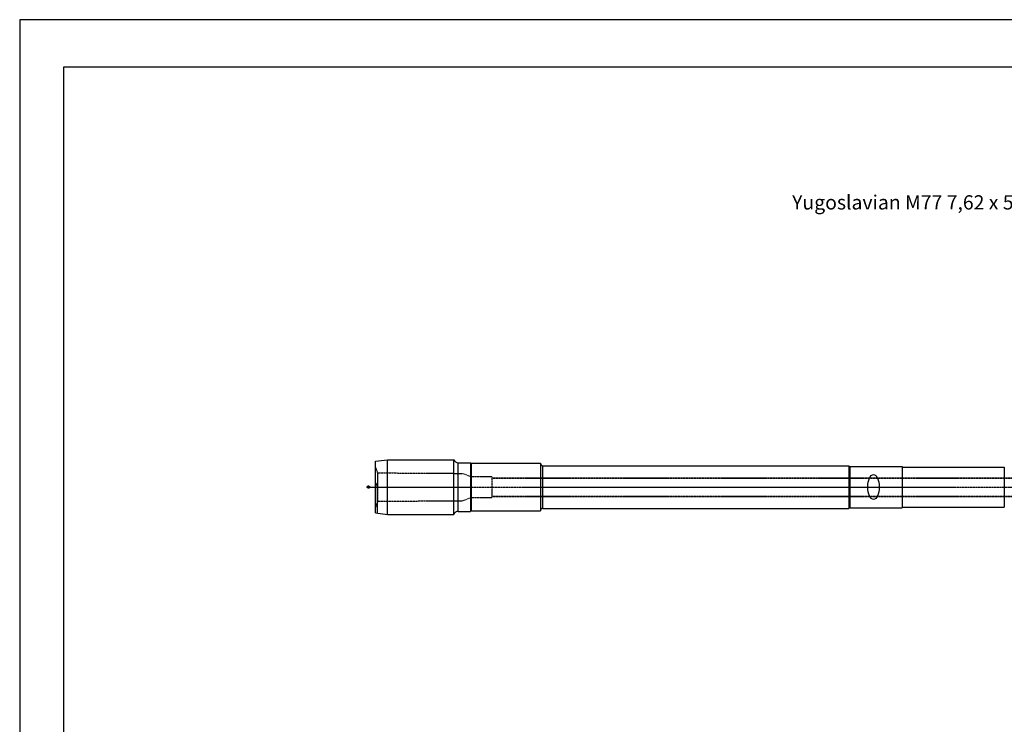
# Model space of a CAD drawing. Units: inches. Extents: x 0 to 841, y 0 to 594.
# Drawn here: x 0 to 415, y 297 to 594 of the extents above; entities that cross this region are included whole.
import ezdxf
from ezdxf.enums import TextEntityAlignment as Align

# ---------------------------------------------------------------- set-up
doc = ezdxf.new("R2010")
doc.units = ezdxf.units.IN
doc.header["$MEASUREMENT"] = 0
doc.linetypes.add('CENTER2', pattern=[1.125, 0.75, -0.125, 0.125, -0.125])
doc.linetypes.add('HIDDEN2', pattern=[0.1875, 0.125, -0.0625])
for name, color, linetype in [('CENTER', 1, 'CENTER2'), ('CENTERLINE', 1, 'CENTER2'), ('HIDDEN', 5, 'HIDDEN2')]:
    doc.layers.add(name, color=color, linetype=linetype)

msp = doc.modelspace()

# ---------------------------------------------------------------- hatches: boundary and pattern name
at = {"layer": 'CENTER'}
h = msp.add_hatch(dxfattribs=at)
h.set_pattern_fill('ANSI31', color=256, style=0)
h.set_pattern_definition([(45, (98, 347), (-0.08838835, 0.08838835), [])])
h.paths.add_polyline_path([(146.99996, 397.50003, 0.414213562), (146.49996, 397.00003), (146.99996, 397.00003)])
h.paths.add_polyline_path([(147.49996, 397.00003), (146.99996, 397.00003), (146.99996, 396.50003, 0.414213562)])

# ---------------------------------------------------------------- linework, layer by layer
for p, q in [((149.99996, 407.92111), (154.99996, 408.53503)), ((149.99996, 386.07895), (149.99996, 407.92111)), ((154.99996, 408.53503), (182.99996, 408.53503)), ((154.99996, 385.46503), (154.99996, 408.53503)), ((182.99996, 385.46503), (182.99996, 408.53503)), ((184.86779, 407.25003), (190.00038, 407.25003)), ((184.86779, 386.75003), (184.86779, 407.25003)), ((190.00038, 407.25003), (190.00038, 386.75003)), ((190.41796, 407.02503), (219.49996, 407.02503)), ((190.41796, 386.97503), (190.41796, 407.02503)), ((219.49996, 407.02503), (219.49996, 386.97503)), ((220.49996, 406.00003), (349.50001, 406.00003)), ((220.49996, 388.00003), (220.49996, 406.00003)), ((349.50001, 406.00003), (349.50001, 388.00003)), ((349.94396, 405.72503), (371.99996, 405.72503)), ((349.94396, 405.72503), (349.94396, 388.27503)), ((371.99996, 405.72503), (371.99996, 388.27503)), ((372.09996, 405.45003), (414.99996, 405.45003)), ((372.09996, 405.45003), (372.09996, 388.55003)), ((414.99996, 405.45003), (414.99996, 388.55003)), ((150.79996, 385.98072), (150.79996, 397.00003)), ((149.99996, 386.07895), (154.99996, 385.46503)), ((184.86779, 386.75003), (190.00038, 386.75003)), ((190.41796, 386.97503), (219.49996, 386.97503)), ((220.49996, 388.00003), (349.50001, 388.00003)), ((349.94396, 388.27503), (371.99996, 388.27503)), ((372.09996, 388.55003), (414.99996, 388.55003)), ((154.99996, 385.46503), (182.99996, 385.46503))]:
    msp.add_line(p, q)
for points in [[(0, 0), (841, 0), (841, 594), (0, 594)], [(18.5, 20), (822.5, 20), (822.5, 574), (18.5, 574)]]:
    msp.add_lwpolyline(points, close=True)
for centre, radius, start, end in [((184.86779, 409.25003), 2, 200.9467416, 270), ((190.41796, 407.52503), 0.5, 213.367013, 270), ((190.41796, 407.52503), 0.5, 213.367013, 270), ((220.49996, 407.00003), 1, 180, 270), ((349.94652, 406.22502), 0.5, 206.7428404, 270), ((372.09996, 405.55003), 0.1, 180, 270), ((415.09996, 405.12503), 0.1, 180, 270), ((148.29996, 397.00003), 2.5, 0, 47.156357), ((184.86779, 384.75003), 2, 90, 159.0532584), ((190.41796, 386.47503), 0.5, 90, 146.632987), ((220.49996, 387.00003), 1, 90, 180), ((349.94396, 387.77503), 0.5, 90, 153.256316), ((372.09996, 388.45003), 0.1, 90, 180), ((415.09996, 388.87503), 0.1, 90, 180)]:
    msp.add_arc(centre, radius, start, end)
msp.add_ellipse((359.94396, 397.00003), major_axis=(0, -5.27871), ratio=0.453419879)
msp.add_line((146.99996, 396.50003), (146.99996, 397.50003), dxfattribs=at)
msp.add_circle((146.99996, 397.00003), 0.5, dxfattribs=at)
at = {"layer": 'CENTERLINE'}
msp.add_line((146.49996, 397.00003), (651.49996, 397.00003), dxfattribs=at)
at = {"layer": 'HIDDEN'}
for p, q in [((151.02957, 402.6712), (149.99996, 405.50003)), ((150.91879, 391.0245), (150.91879, 402.97556)), ((150.91879, 402.97556), (186.6124, 402.76507)), ((186.6124, 402.76507), (190.41796, 401.38601)), ((190.41796, 401.38601), (199.17996, 401.38601)), ((199.17996, 392.64003), (199.17996, 401.38601)), ((199.17996, 400.91003), (649.99996, 400.91003)), ((199.17996, 400.81003), (649.99996, 400.81003)), ((150.91879, 391.0245), (149.99996, 388.50003)), ((150.91879, 391.0245), (186.6124, 391.23498)), ((186.6124, 391.23498), (190.41796, 392.61405)), ((190.41796, 392.61405), (199.17996, 392.61405)), ((199.17996, 393.19003), (649.99996, 393.19003)), ((199.17996, 393.09003), (649.99996, 393.09003))]:
    msp.add_line(p, q, dxfattribs=at)

# ---------------------------------------------------------------- texts
msp.add_text('Yugoslavian M77 7,62 x 51,0', height=6).set_placement((378, 517), align=Align.MIDDLE_CENTER)

doc.saveas('drawing.dxf')
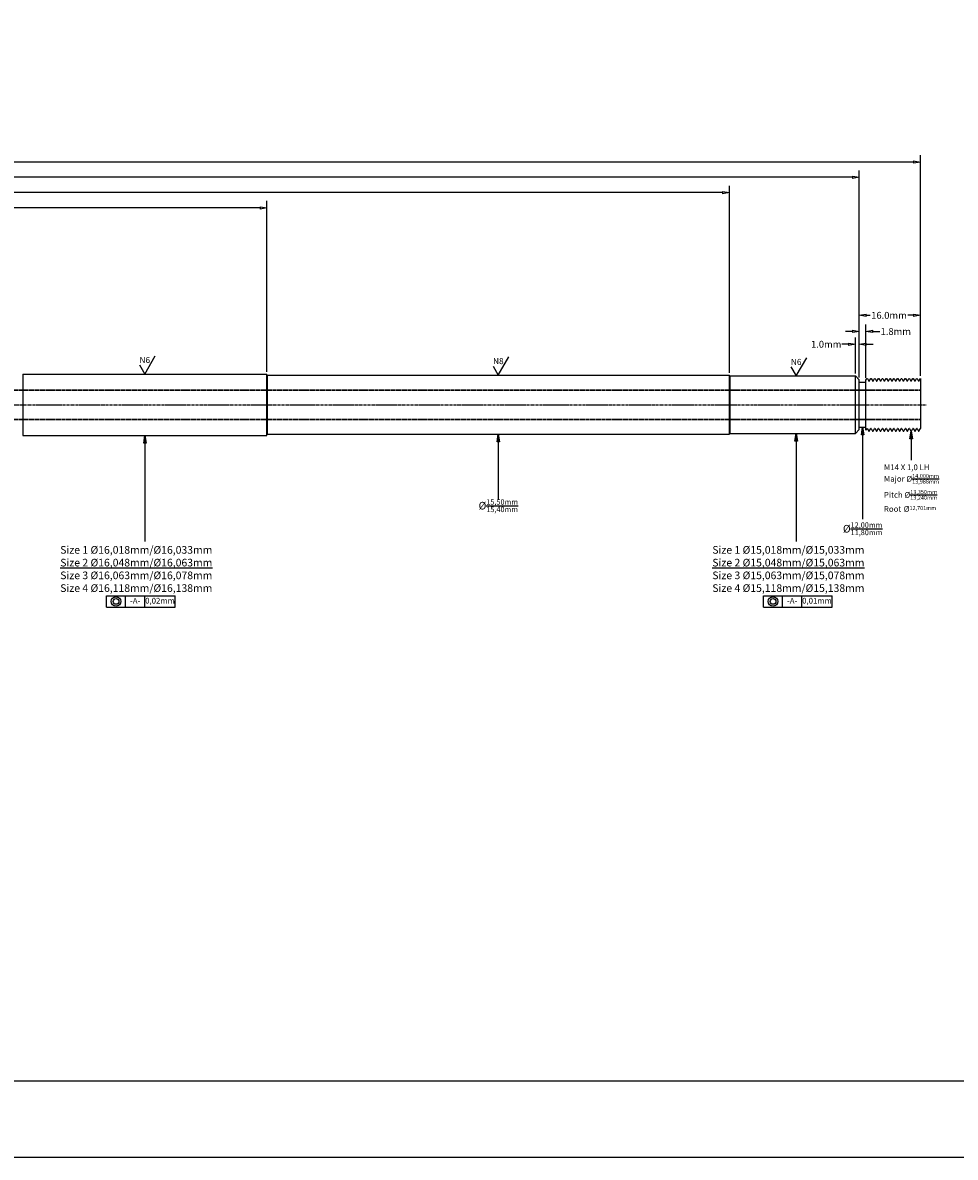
# Model space of a CAD drawing. Units: inches. Extents: x 0 to 841, y 0 to 594.
# Drawn here: x 415 to 659, y 0 to 297 of the extents above; entities that cross this region are included whole.
import ezdxf
from ezdxf.enums import TextEntityAlignment as Align

# ---------------------------------------------------------------- set-up
doc = ezdxf.new("R2010")
doc.units = ezdxf.units.IN
doc.header["$MEASUREMENT"] = 0
doc.linetypes.add('CENTER2', pattern=[1.125, 0.75, -0.125, 0.125, -0.125])
doc.linetypes.add('HIDDEN2', pattern=[0.1875, 0.125, -0.0625])
for name, color, linetype in [('CENTERLINE', 1, 'CENTER2'), ('HIDDEN', 5, 'HIDDEN2'), ('TEXT', 5, 'Continuous')]:
    doc.layers.add(name, color=color, linetype=linetype)
doc.dimstyles.get("Standard").update_dxf_attribs({"dimscale": 10, "dimtxt": 0.18, "dimasz": 0.18, "dimexe": 0.18, "dimexo": 0.0625, "dimgap": 0.09, "dimtad": 0, "dimtih": 1, "dimtoh": 1, "dimdec": 4, "dimzin": 0, "dimdsep": 46, "dimtxsty": 'Standard', "dimblk": 'CLOSEDBLANK', "dimcen": 0.09, "dimadec": 4, "dimazin": 0, "dimtfac": 1, "dimtdec": 4, "dimtofl": 0, "dimtmove": 0, "dimatfit": 3, "dimldrblk": 'CLOSEDBLANK', "dimfxl": 0, "dimtolj": 1, "dimtzin": 0, "dimarcsym": 0})
doc.dimstyles.new('Standard$0', dxfattribs={"dimscale": 10, "dimtxt": 0.18, "dimasz": 0.18, "dimexe": 0.18, "dimexo": 0.0625, "dimgap": 0.09, "dimtad": 0, "dimtih": 1, "dimtoh": 1, "dimdec": 4, "dimzin": 4, "dimdsep": 46, "dimtxsty": 'Standard', "dimblk": 'CLOSEDBLANK', "dimcen": 0.09, "dimadec": 5, "dimazin": 1, "dimtfac": 1, "dimtdec": 4, "dimtofl": 0, "dimtmove": 0, "dimatfit": 3, "dimldrblk": 'CLOSEDBLANK', "dimfxl": 0, "dimtolj": 1, "dimtzin": 0, "dimarcsym": 0})

# ---------------------------------------------------------------- blocks, each defined once
blk = doc.blocks.new('_ClosedBlank')
at = {"color": 0, "linetype": 'ByBlock', "lineweight": -2}
for p, q in [((-1, 0.17), (0, 0)), ((-1, 0.17), (-1, -0.17)), ((0, 0), (-1, -0.17))]:
    blk.add_line(p, q, dxfattribs=at)
blk = doc.blocks.new('*D21')
at = {"color": 0, "lineweight": -2}
for p, q in [((634, 204.15), (634, 222.2)), ((635.8, 220.4), (636.83, 220.4)), ((648.2, 220.4), (646.73, 220.4)), ((650, 204.52), (650, 222.2))]:
    blk.add_line(p, q, dxfattribs=at)
at = {"layer": 'Defpoints', "color": 0}
for p in [(650, 220.4), (634, 203.53), (650, 203.89)]:
    blk.add_point(p, dxfattribs=at)
at = {"color": 0, "lineweight": -2, "xscale": 1.8, "yscale": 1.8, "zscale": 1.8, "rotation": 180}
blk.add_blockref('_ClosedBlank', (634, 220.4), dxfattribs=at)
at = {"color": 0, "lineweight": -2, "xscale": 1.8, "yscale": 1.8, "zscale": 1.8}
blk.add_blockref('_ClosedBlank', (650, 220.4), dxfattribs=at)
at = {"color": 0, "insert": (641.78, 220.4), "char_height": 1.8, "attachment_point": 5}
blk.add_mtext('\\A1;16.0mm', dxfattribs=at)
blk = doc.blocks.new('*D15')
at = {"color": 0, "lineweight": -2}
for p, q in [((150, 208.55), (150, 250.33)), ((479, 205.65), (479, 250.33)), ((151.8, 248.53), (308.35, 248.53)), ((477.2, 248.53), (320.65, 248.53))]:
    blk.add_line(p, q, dxfattribs=at)
at = {"layer": 'Defpoints', "color": 0}
for p in [(150, 248.53), (150, 207.92), (479, 205.03)]:
    blk.add_point(p, dxfattribs=at)
at = {"color": 0, "lineweight": -2, "xscale": 1.8, "yscale": 1.8, "zscale": 1.8, "rotation": 180}
blk.add_blockref('_ClosedBlank', (150, 248.53), dxfattribs=at)
at = {"color": 0, "lineweight": -2, "xscale": 1.8, "yscale": 1.8, "zscale": 1.8}
blk.add_blockref('_ClosedBlank', (479, 248.53), dxfattribs=at)
at = {"color": 0, "insert": (314.5, 248.53), "char_height": 1.8, "attachment_point": 5}
blk.add_mtext('\\A1;329.0mm', dxfattribs=at)
blk = doc.blocks.new('*D16')
at = {"color": 0, "lineweight": -2}
for p, q in [((150, 208.55), (150, 254.33)), ((151.8, 252.53), (369, 252.53)), ((598.2, 252.53), (381, 252.53)), ((600, 205.38), (600, 254.33))]:
    blk.add_line(p, q, dxfattribs=at)
at = {"layer": 'Defpoints', "color": 0}
for p in [(150, 252.53), (150, 207.92), (600, 204.75)]:
    blk.add_point(p, dxfattribs=at)
at = {"color": 0, "lineweight": -2, "xscale": 1.8, "yscale": 1.8, "zscale": 1.8, "rotation": 180}
blk.add_blockref('_ClosedBlank', (150, 252.53), dxfattribs=at)
at = {"color": 0, "lineweight": -2, "xscale": 1.8, "yscale": 1.8, "zscale": 1.8}
blk.add_blockref('_ClosedBlank', (600, 252.53), dxfattribs=at)
at = {"color": 0, "insert": (375, 252.53), "char_height": 1.8, "attachment_point": 5}
blk.add_mtext('\\A1;450.0mm', dxfattribs=at)
blk = doc.blocks.new('*D17')
at = {"color": 0, "lineweight": -2}
for p, q in [((150, 208.55), (150, 258.33)), ((151.8, 256.53), (385.85, 256.53)), ((632.2, 256.53), (398.15, 256.53)), ((634, 204.15), (634, 258.33))]:
    blk.add_line(p, q, dxfattribs=at)
at = {"layer": 'Defpoints', "color": 0}
for p in [(150, 256.53), (150, 207.92), (634, 203.53)]:
    blk.add_point(p, dxfattribs=at)
at = {"color": 0, "lineweight": -2, "xscale": 1.8, "yscale": 1.8, "zscale": 1.8, "rotation": 180}
blk.add_blockref('_ClosedBlank', (150, 256.53), dxfattribs=at)
at = {"color": 0, "lineweight": -2, "xscale": 1.8, "yscale": 1.8, "zscale": 1.8}
blk.add_blockref('_ClosedBlank', (634, 256.53), dxfattribs=at)
at = {"color": 0, "insert": (392, 256.53), "char_height": 1.8, "attachment_point": 5}
blk.add_mtext('\\A1;484.0mm', dxfattribs=at)
blk = doc.blocks.new('*D18')
at = {"color": 0, "lineweight": -2}
for p, q in [((150, 208.55), (150, 262.33)), ((650, 204.52), (650, 262.33)), ((151.8, 260.53), (394.15, 260.53)), ((648.2, 260.53), (405.85, 260.53))]:
    blk.add_line(p, q, dxfattribs=at)
at = {"layer": 'Defpoints', "color": 0}
for p in [(650, 260.53), (150, 207.92), (650, 203.89)]:
    blk.add_point(p, dxfattribs=at)
at = {"color": 0, "lineweight": -2, "xscale": 1.8, "yscale": 1.8, "zscale": 1.8, "rotation": 180}
blk.add_blockref('_ClosedBlank', (150, 260.53), dxfattribs=at)
at = {"color": 0, "lineweight": -2, "xscale": 1.8, "yscale": 1.8, "zscale": 1.8}
blk.add_blockref('_ClosedBlank', (650, 260.53), dxfattribs=at)
at = {"color": 0, "insert": (400, 260.53), "char_height": 1.8, "attachment_point": 5}
blk.add_mtext('\\A1;500.0mm', dxfattribs=at)
blk = doc.blocks.new('*D19')
at = {"color": 0, "lineweight": -2}
for p, q in [((634, 204.15), (634, 217.97)), ((635.75, 204.08), (635.75, 217.97)), ((632.2, 216.17), (630.4, 216.17)), ((637.55, 216.17), (639.35, 216.17))]:
    blk.add_line(p, q, dxfattribs=at)
at = {"layer": 'Defpoints', "color": 0}
for p in [(635.75, 216.17), (634, 203.53), (635.75, 203.46)]:
    blk.add_point(p, dxfattribs=at)
at = {"color": 0, "lineweight": -2, "xscale": 1.8, "yscale": 1.8, "zscale": 1.8}
blk.add_blockref('_ClosedBlank', (634, 216.17), dxfattribs=at)
at = {"color": 0, "lineweight": -2, "xscale": 1.8, "yscale": 1.8, "zscale": 1.8, "rotation": 180}
blk.add_blockref('_ClosedBlank', (635.75, 216.17), dxfattribs=at)
at = {"color": 0, "insert": (643.55, 216.17), "char_height": 1.8, "attachment_point": 5}
blk.add_mtext('\\A1;1.8mm', dxfattribs=at)
blk = doc.blocks.new('*D20')
at = {"color": 0, "lineweight": -2}
for p, q in [((633, 205.15), (633, 214.62)), ((634, 204.15), (634, 214.62)), ((631.2, 212.82), (629.4, 212.82)), ((635.8, 212.82), (637.6, 212.82))]:
    blk.add_line(p, q, dxfattribs=at)
at = {"layer": 'Defpoints', "color": 0}
for p in [(633, 212.82), (633, 204.53), (634, 203.53)]:
    blk.add_point(p, dxfattribs=at)
at = {"color": 0, "lineweight": -2, "xscale": 1.8, "yscale": 1.8, "zscale": 1.8}
blk.add_blockref('_ClosedBlank', (633, 212.82), dxfattribs=at)
at = {"color": 0, "lineweight": -2, "xscale": 1.8, "yscale": 1.8, "zscale": 1.8, "rotation": 180}
blk.add_blockref('_ClosedBlank', (634, 212.82), dxfattribs=at)
at = {"color": 0, "insert": (625.35, 212.82), "char_height": 1.8, "attachment_point": 5}
blk.add_mtext('\\A1;1.0mm', dxfattribs=at)

msp = doc.modelspace()

# ---------------------------------------------------------------- linework, layer by layer
for p, q in [((447.04996, 205.02503), (449.79959, 209.78753)), ((539.54996, 204.75003), (542.29959, 209.51253)), ((617.49996, 204.52503), (620.24959, 209.28753)), ((415.09996, 205.02503), (478.99996, 205.02503)), ((415.09996, 205.02503), (415.09996, 188.97503)), ((445.67514, 207.40628), (447.04996, 205.02503)), ((478.99996, 188.97503), (478.99996, 205.02503)), ((538.17514, 207.13128), (539.54996, 204.75003)), ((616.12515, 206.90628), (617.49996, 204.52503)), ((479.09996, 204.75003), (599.99996, 204.75003)), ((479.09996, 204.75003), (479.09996, 189.25003)), ((599.99996, 189.25003), (599.99996, 204.75003)), ((599.99996, 189.25003), (599.99996, 204.75003)), ((600.09996, 204.52503), (632.99996, 204.52503)), ((600.09996, 204.52503), (600.09996, 189.47503)), ((632.99996, 189.47503), (632.99996, 204.52503)), ((632.99996, 204.52503), (633.99996, 203.52503)), ((633.99996, 190.47503), (633.99996, 203.52503)), ((633.99996, 202.90003), (635.74996, 202.90003)), ((635.74996, 203.45876), (635.99996, 203.89178)), ((635.74996, 190.32479), (635.74996, 203.45876)), ((635.99996, 203.89178), (636.12496, 203.89178)), ((636.12496, 203.89178), (636.5208, 203.20617)), ((636.49996, 203.24226), (636.5208, 203.20617)), ((636.5208, 203.20617), (636.60413, 203.20617)), ((636.60413, 203.20617), (636.5208, 203.20617)), ((636.60413, 203.20617), (636.99996, 203.89178)), ((636.99996, 203.89178), (637.12496, 203.89178)), ((637.12496, 203.89178), (637.5208, 203.20617)), ((637.49996, 203.24226), (637.5208, 203.20617)), ((637.5208, 203.20617), (637.60413, 203.20617)), ((637.60413, 203.20617), (637.5208, 203.20617)), ((637.60413, 203.20617), (637.99996, 203.89178)), ((637.99996, 203.89178), (638.12496, 203.89178)), ((638.12496, 203.89178), (638.5208, 203.20617)), ((638.5208, 203.20617), (638.60413, 203.20617)), ((638.60413, 203.20617), (638.5208, 203.20617)), ((638.60413, 203.20617), (638.99996, 203.89178)), ((638.99996, 203.89178), (639.12496, 203.89178)), ((639.12496, 203.89178), (639.5208, 203.20617)), ((639.60413, 203.20617), (639.5208, 203.20617)), ((639.60413, 203.20617), (639.99996, 203.89178)), ((639.99996, 203.89178), (640.12496, 203.89178)), ((640.12496, 203.89178), (640.5208, 203.20617)), ((640.60413, 203.20617), (640.5208, 203.20617)), ((640.60413, 203.20617), (640.99996, 203.89178)), ((640.99996, 203.89178), (641.12496, 203.89178)), ((641.12496, 203.89178), (641.5208, 203.20617)), ((641.60413, 203.20617), (641.5208, 203.20617)), ((641.60413, 203.20617), (641.99996, 203.89178)), ((641.99996, 203.89178), (642.12496, 203.89178)), ((642.12496, 203.89178), (642.5208, 203.20617)), ((642.60413, 203.20617), (642.5208, 203.20617)), ((642.60413, 203.20617), (642.99996, 203.89178)), ((642.99996, 203.89178), (643.12496, 203.89178)), ((643.12496, 203.89178), (643.5208, 203.20617)), ((643.60413, 203.20617), (643.5208, 203.20617)), ((643.60413, 203.20617), (643.99996, 203.89178)), ((643.99996, 203.89178), (644.12496, 203.89178)), ((644.12496, 203.89178), (644.5208, 203.20617)), ((644.60413, 203.20617), (644.5208, 203.20617)), ((644.60413, 203.20617), (644.99996, 203.89178)), ((644.99996, 203.89178), (645.12496, 203.89178)), ((645.12496, 203.89178), (645.5208, 203.20617)), ((645.60413, 203.20617), (645.5208, 203.20617)), ((645.60413, 203.20617), (645.99996, 203.89178)), ((645.99996, 203.89178), (646.12496, 203.89178)), ((646.12496, 203.89178), (646.5208, 203.20617)), ((646.60413, 203.20617), (646.5208, 203.20617)), ((646.60413, 203.20617), (646.99996, 203.89178)), ((646.99996, 203.89178), (647.12496, 203.89178)), ((647.12496, 203.89178), (647.5208, 203.20617)), ((647.60413, 203.20617), (647.5208, 203.20617)), ((647.60413, 203.20617), (647.99996, 203.89178)), ((647.99996, 203.89178), (648.12496, 203.89178)), ((648.12496, 203.89178), (648.5208, 203.20617)), ((648.60413, 203.20617), (648.5208, 203.20617)), ((648.60413, 203.20617), (648.99996, 203.89178)), ((648.99996, 203.89178), (649.12496, 203.89178)), ((649.12496, 203.89178), (649.5208, 203.20617)), ((649.60413, 203.20617), (649.5208, 203.20617)), ((649.60413, 203.20617), (649.99996, 203.89178)), ((649.99996, 203.89178), (649.99996, 190.7578)), ((632.99996, 189.47503), (633.99996, 190.47503)), ((633.99996, 191.10003), (635.74996, 191.10003)), ((635.74996, 190.32479), (636.0208, 190.79389)), ((636.0208, 190.79389), (636.10413, 190.79389)), ((636.10413, 190.79389), (636.0208, 190.79389)), ((636.10413, 190.79389), (636.49996, 190.10828)), ((636.49996, 190.10828), (636.62496, 190.10828)), ((636.62496, 190.10828), (637.0208, 190.79389)), ((637.0208, 190.79389), (637.10413, 190.79389)), ((637.10413, 190.79389), (637.0208, 190.79389)), ((637.10413, 190.79389), (637.49996, 190.10828)), ((637.49996, 190.10828), (637.62496, 190.10828)), ((637.62496, 190.10828), (638.0208, 190.79389)), ((638.0208, 190.79389), (638.10413, 190.79389)), ((638.10413, 190.79389), (638.0208, 190.79389)), ((638.10413, 190.79389), (638.49996, 190.10828)), ((638.49996, 190.10828), (638.62496, 190.10828)), ((638.62496, 190.10828), (639.0208, 190.79389)), ((639.10413, 190.79389), (639.0208, 190.79389)), ((639.10413, 190.79389), (639.49996, 190.10828)), ((639.49996, 190.10828), (639.62496, 190.10828)), ((639.62496, 190.10828), (640.0208, 190.79389)), ((640.10413, 190.79389), (640.0208, 190.79389)), ((640.10413, 190.79389), (640.49996, 190.10828)), ((640.49996, 190.10828), (640.62496, 190.10828)), ((640.62496, 190.10828), (641.0208, 190.79389)), ((641.10413, 190.79389), (641.0208, 190.79389)), ((641.10413, 190.79389), (641.49996, 190.10828)), ((641.49996, 190.10828), (641.62496, 190.10828)), ((641.62496, 190.10828), (642.0208, 190.79389)), ((642.10413, 190.79389), (642.0208, 190.79389)), ((642.10413, 190.79389), (642.49996, 190.10828)), ((642.49996, 190.10828), (642.62496, 190.10828)), ((642.62496, 190.10828), (643.0208, 190.79389)), ((643.10413, 190.79389), (643.0208, 190.79389)), ((643.10413, 190.79389), (643.49996, 190.10828)), ((643.49996, 190.10828), (643.62496, 190.10828)), ((643.62496, 190.10828), (644.0208, 190.79389)), ((644.10413, 190.79389), (644.0208, 190.79389)), ((644.10413, 190.79389), (644.49996, 190.10828)), ((644.49996, 190.10828), (644.62496, 190.10828)), ((644.62496, 190.10828), (645.0208, 190.79389)), ((645.10413, 190.79389), (645.0208, 190.79389)), ((645.10413, 190.79389), (645.49996, 190.10828)), ((645.49996, 190.10828), (645.62496, 190.10828)), ((645.62496, 190.10828), (646.0208, 190.79389)), ((646.10413, 190.79389), (646.0208, 190.79389)), ((646.10413, 190.79389), (646.49996, 190.10828)), ((646.49996, 190.10828), (646.62496, 190.10828)), ((646.62496, 190.10828), (647.0208, 190.79389)), ((647.10413, 190.79389), (647.0208, 190.79389)), ((647.10413, 190.79389), (647.49996, 190.10828)), ((647.49996, 190.10828), (647.62496, 190.10828)), ((647.62496, 190.10828), (648.0208, 190.79389)), ((648.10413, 190.79389), (648.0208, 190.79389)), ((648.10413, 190.79389), (648.49996, 190.10828)), ((648.49996, 190.10828), (648.62496, 190.10828)), ((648.62496, 190.10828), (649.0208, 190.79389)), ((649.10413, 190.79389), (649.0208, 190.79389)), ((649.10413, 190.79389), (649.49996, 190.10828)), ((649.49996, 190.10828), (649.62496, 190.10828)), ((649.62496, 190.10828), (649.99996, 190.7578)), ((415.09996, 188.97503), (478.99996, 188.97503)), ((479.09996, 189.25003), (599.99996, 189.25003)), ((600.09996, 189.47503), (632.99996, 189.47503))]:
    msp.add_line(p, q)
for points in [[(0, 0), (841, 0), (841, 594), (0, 594)], [(18.5, 20), (822.5, 20), (822.5, 574), (18.5, 574)]]:
    msp.add_lwpolyline(points, close=True)
for centre, start, end in [((479.09996, 204.85003), 180, 270), ((600.09996, 204.62503), 180, 270), ((479.09996, 189.15003), 90, 180), ((600.09996, 189.37503), 90, 180)]:
    msp.add_arc(centre, 0.1, start, end)
at = {"layer": 'CENTERLINE'}
msp.add_line((146.49996, 197.00003), (651.49996, 197.00003), dxfattribs=at)
at = {"layer": 'HIDDEN'}
for p, q in [((199.17996, 200.91003), (649.99996, 200.91003)), ((199.17996, 200.81003), (649.99996, 200.81003)), ((199.17996, 193.19003), (649.99996, 193.19003)), ((199.17996, 193.09003), (649.99996, 193.09003))]:
    msp.add_line(p, q, dxfattribs=at)
at = {"layer": 'TEXT', "color": 7}
for p, q in [((437.02424, 144), (437.02424, 147)), ((437.02424, 147), (442.02424, 147)), ((442.02424, 147), (447.02424, 147)), ((442.02424, 144), (442.02424, 147)), ((447.02424, 147), (455.02424, 147)), ((447.02424, 144), (447.02424, 147)), ((455.02424, 144), (455.02424, 147)), ((608.93457, 144), (608.93457, 147)), ((608.93457, 147), (613.93457, 147)), ((613.93457, 147), (618.93457, 147)), ((613.93457, 144), (613.93457, 147)), ((618.93457, 147), (626.93457, 147)), ((618.93457, 144), (618.93457, 147)), ((626.93457, 144), (626.93457, 147)), ((437.02424, 144), (442.02424, 144)), ((442.02424, 144), (447.02424, 144)), ((447.02424, 144), (455.02424, 144)), ((608.93457, 144), (613.93457, 144)), ((613.93457, 144), (618.93457, 144)), ((618.93457, 144), (626.93457, 144))]:
    msp.add_line(p, q, dxfattribs=at)
for centre, radius in [((439.52424, 145.5), 1.25), ((439.52424, 145.5), 0.75), ((611.43457, 145.5), 1.25), ((611.43457, 145.5), 0.75)]:
    msp.add_circle(centre, radius, dxfattribs=at)

# ---------------------------------------------------------------- texts
for s, p in [('N6', (447.04996, 207.40628)), ('N8', (539.54996, 207.13128)), ('N6', (617.49996, 206.90628))]:
    msp.add_text(s, height=1.5875).set_placement(p, align=Align.BOTTOM_CENTER)
at = {"char_height": 2, "width": 10.5482646, "attachment_point": 2}
for s, insert in [('\\A1;%%C{\\H0.7x;\\S15,50mm/15,40mm;}', (539.54996, 172.25003)), ('\\A1;%%C{\\H0.7x;\\S12,00mm/11,80mm;}', (634.87496, 166.21478))]:
    msp.add_mtext(s, dxfattribs=dict(at, insert=insert))
at = {"layer": 'TEXT', "color": 7}
for s, insert, char_height, width, attachment_point in [('\\A1;{\\H0.75x;M14 X 1,0 LH\\PMajor %%C\\H0.7x;\\S14,000mm/13,988mm;\\H1.429x;\\PPitch %%C\\H0.7x;\\S13,350mm/13,240mm;\\H1.429x;\\PRoot} {\\H0.75x;%%C\\H0.7x;12,701mm}', (640.45201, 181.37094), 2, 19.3860592, 1), ('\\A1;Size 1 %%C16,018mm/%%C16,033mm\\P{\\LSize 2 %%C16,048mm/%%C16,063mm}\\PSize 3 %%C16,063mm/%%C16,078mm\\PSize 4 %%C16,118mm/%%C16,138mm', (424.91639, 160), 2, 48.5376086, 1), ('\\A1;Size 1 %%C15,018mm/%%C15,033mm\\P{\\LSize 2 %%C15,048mm/%%C15,063mm}\\PSize 3 %%C15,063mm/%%C15,078mm\\PSize 4 %%C15,118mm/%%C15,138mm', (595.54315, 160), 2, 48.5376086, 1), ('-A-', (444.52424, 145.5), 1.5, 1.19634, 5), ('0,02mm', (451.02424, 145.5), 1.5, 6.6720954, 5), ('-A-', (616.43457, 145.5), 1.5, 1.19634, 5), ('0,01mm', (622.93457, 145.5), 1.5, 6.6720954, 5)]:
    msp.add_mtext(s, dxfattribs=dict(at, insert=insert, char_height=char_height, width=width, attachment_point=attachment_point))

# ---------------------------------------------------------------- dimensions: what is measured, and where the dimension line sits
for base, p1, p2, picture, middle in [((649.99996, 260.52503), (149.99996, 207.92111), (649.99996, 203.89178), '*D18', (399.99996, 260.52503)), ((149.99996, 256.52503), (633.99996, 203.52503), (149.99996, 207.92111), '*D17', (391.99996, 256.52503)), ((149.99996, 252.52503), (599.99996, 204.75003), (149.99996, 207.92111), '*D16', (374.99996, 252.52503)), ((149.99996, 248.52503), (478.99996, 205.02503), (149.99996, 207.92111), '*D15', (314.49996, 248.52503)), ((635.7499623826, 216.1660716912), (633.9999623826, 203.5250289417), (635.7499623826, 203.4587630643), '*D19', (643.5499623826, 216.1660716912))]:
    dim = msp.add_linear_dim(base=base, p1=p1, p2=p2, dimstyle='Standard$0', override={"dimscale": 10, "dimdec": 1, "dimpost": 'mm', "dimblk1": 'ClosedBlank', "dimblk2": 'ClosedBlank', "dimsah": 1})
    dim.commit()
    dim.dimension.update_dxf_attribs({"geometry": picture, "text_midpoint": middle})
dim = msp.add_linear_dim(base=(649.99996, 220.40166), p1=(633.99996, 203.52503), p2=(649.99996, 203.89178), dimstyle='Standard$0', override={"dimscale": 10, "dimdec": 1, "dimpost": 'mm', "dimblk1": 'ClosedBlank', "dimblk2": 'ClosedBlank', "dimsah": 1})
dim.commit()
dim.dimension.update_dxf_attribs({"geometry": '*D21', "text_midpoint": (641.78494, 220.40166), "dimtype": 160})
dim = msp.add_linear_dim(base=(632.99996, 212.81887), p1=(633.99996, 203.52503), p2=(632.99996, 204.52503), angle=180, dimstyle='Standard$0', override={"dimscale": 10, "dimdec": 1, "dimpost": 'mm', "dimblk1": 'ClosedBlank', "dimblk2": 'ClosedBlank', "dimsah": 1})
dim.commit()
dim.dimension.update_dxf_attribs({"geometry": '*D20', "text_midpoint": (625.34996, 212.81887)})

# ---------------------------------------------------------------- leaders
for points in [[(634.87496, 191.10003), (634.87496, 167.08332)], [(647.56246, 190.10828), (647.56246, 182.45928)], [(539.54996, 189.25003), (539.54996, 172.25003)]]:
    msp.add_leader(points, dimstyle='Standard', override={"dimscale": 1, "dimasz": 2, "dimgap": 0.09, "dimtad": 0, "dimldrblk": 'ClosedBlank'})
for points in [[(447.09996, 188.97503), (447.09996, 161.23901)], [(617.49996, 189.47503), (617.49996, 161.23901)]]:
    msp.add_leader(points, dimstyle='Standard', override={"dimscale": 1, "dimasz": 2, "dimgap": 0.09, "dimtad": 0, "dimldrblk": 'ClosedBlank'}, dxfattribs=at)

doc.saveas('drawing.dxf')
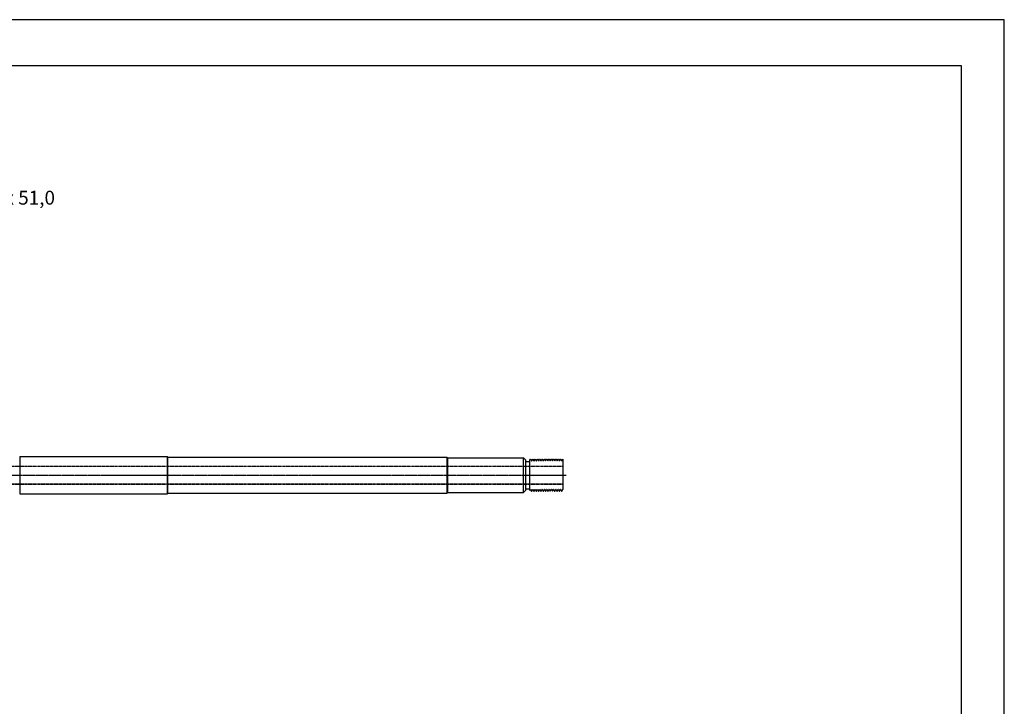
# Model space of a CAD drawing. Units: inches. Extents: x 0 to 841, y 0 to 594.
# Drawn here: x 415 to 841, y 297 to 594 of the extents above; entities that cross this region are included whole.
import ezdxf
from ezdxf.enums import TextEntityAlignment as Align

# ---------------------------------------------------------------- set-up
doc = ezdxf.new("R2010")
doc.units = ezdxf.units.IN
doc.header["$MEASUREMENT"] = 0
doc.linetypes.add('CENTER2', pattern=[1.125, 0.75, -0.125, 0.125, -0.125])
doc.linetypes.add('HIDDEN2', pattern=[0.1875, 0.125, -0.0625])
doc.layers.add('CENTERLINE', color=1, linetype='CENTER2')
doc.layers.add('HIDDEN', color=5, linetype='HIDDEN2')

msp = doc.modelspace()

# ---------------------------------------------------------------- linework, layer by layer
for p, q in [((415.09996, 405.02503), (478.99996, 405.02503)), ((415.09996, 405.02503), (415.09996, 388.97503)), ((478.99996, 388.97503), (478.99996, 405.02503)), ((479.09996, 404.75003), (599.99996, 404.75003)), ((479.09996, 404.75003), (479.09996, 389.25003)), ((599.99996, 389.25003), (599.99996, 404.75003)), ((599.99996, 389.25003), (599.99996, 404.75003)), ((600.09996, 404.52503), (632.99996, 404.52503)), ((600.09996, 404.52503), (600.09996, 389.47503)), ((632.99996, 389.47503), (632.99996, 404.52503)), ((632.99996, 404.52503), (633.99996, 403.52503)), ((633.99996, 390.47503), (633.99996, 403.52503)), ((633.99996, 402.90003), (635.74996, 402.90003)), ((635.74996, 403.45876), (635.99996, 403.89178)), ((635.74996, 390.32479), (635.74996, 403.45876)), ((635.99996, 403.89178), (636.12496, 403.89178)), ((636.12496, 403.89178), (636.5208, 403.20617)), ((636.49996, 403.24226), (636.5208, 403.20617)), ((636.5208, 403.20617), (636.60413, 403.20617)), ((636.60413, 403.20617), (636.5208, 403.20617)), ((636.60413, 403.20617), (636.99996, 403.89178)), ((636.99996, 403.89178), (637.12496, 403.89178)), ((637.12496, 403.89178), (637.5208, 403.20617)), ((637.49996, 403.24226), (637.5208, 403.20617)), ((637.5208, 403.20617), (637.60413, 403.20617)), ((637.60413, 403.20617), (637.5208, 403.20617)), ((637.60413, 403.20617), (637.99996, 403.89178)), ((637.99996, 403.89178), (638.12496, 403.89178)), ((638.12496, 403.89178), (638.5208, 403.20617)), ((638.5208, 403.20617), (638.60413, 403.20617)), ((638.60413, 403.20617), (638.5208, 403.20617)), ((638.60413, 403.20617), (638.99996, 403.89178)), ((638.99996, 403.89178), (639.12496, 403.89178)), ((639.12496, 403.89178), (639.5208, 403.20617)), ((639.60413, 403.20617), (639.5208, 403.20617)), ((639.60413, 403.20617), (639.99996, 403.89178)), ((639.99996, 403.89178), (640.12496, 403.89178)), ((640.12496, 403.89178), (640.5208, 403.20617)), ((640.60413, 403.20617), (640.5208, 403.20617)), ((640.60413, 403.20617), (640.99996, 403.89178)), ((640.99996, 403.89178), (641.12496, 403.89178)), ((641.12496, 403.89178), (641.5208, 403.20617)), ((641.60413, 403.20617), (641.5208, 403.20617)), ((641.60413, 403.20617), (641.99996, 403.89178)), ((641.99996, 403.89178), (642.12496, 403.89178)), ((642.12496, 403.89178), (642.5208, 403.20617)), ((642.60413, 403.20617), (642.5208, 403.20617)), ((642.60413, 403.20617), (642.99996, 403.89178)), ((642.99996, 403.89178), (643.12496, 403.89178)), ((643.12496, 403.89178), (643.5208, 403.20617)), ((643.60413, 403.20617), (643.5208, 403.20617)), ((643.60413, 403.20617), (643.99996, 403.89178)), ((643.99996, 403.89178), (644.12496, 403.89178)), ((644.12496, 403.89178), (644.5208, 403.20617)), ((644.60413, 403.20617), (644.5208, 403.20617)), ((644.60413, 403.20617), (644.99996, 403.89178)), ((644.99996, 403.89178), (645.12496, 403.89178)), ((645.12496, 403.89178), (645.5208, 403.20617)), ((645.60413, 403.20617), (645.5208, 403.20617)), ((645.60413, 403.20617), (645.99996, 403.89178)), ((645.99996, 403.89178), (646.12496, 403.89178)), ((646.12496, 403.89178), (646.5208, 403.20617)), ((646.60413, 403.20617), (646.5208, 403.20617)), ((646.60413, 403.20617), (646.99996, 403.89178)), ((646.99996, 403.89178), (647.12496, 403.89178)), ((647.12496, 403.89178), (647.5208, 403.20617)), ((647.60413, 403.20617), (647.5208, 403.20617)), ((647.60413, 403.20617), (647.99996, 403.89178)), ((647.99996, 403.89178), (648.12496, 403.89178)), ((648.12496, 403.89178), (648.5208, 403.20617)), ((648.60413, 403.20617), (648.5208, 403.20617)), ((648.60413, 403.20617), (648.99996, 403.89178)), ((648.99996, 403.89178), (649.12496, 403.89178)), ((649.12496, 403.89178), (649.5208, 403.20617)), ((649.60413, 403.20617), (649.5208, 403.20617)), ((649.60413, 403.20617), (649.99996, 403.89178)), ((649.99996, 403.89178), (649.99996, 390.7578)), ((415.09996, 388.97503), (478.99996, 388.97503)), ((479.09996, 389.25003), (599.99996, 389.25003)), ((600.09996, 389.47503), (632.99996, 389.47503)), ((632.99996, 389.47503), (633.99996, 390.47503)), ((633.99996, 391.10003), (635.74996, 391.10003)), ((635.74996, 390.32479), (636.0208, 390.79389)), ((636.0208, 390.79389), (636.10413, 390.79389)), ((636.10413, 390.79389), (636.0208, 390.79389)), ((636.10413, 390.79389), (636.49996, 390.10828)), ((636.49996, 390.10828), (636.62496, 390.10828)), ((636.62496, 390.10828), (637.0208, 390.79389)), ((637.0208, 390.79389), (637.10413, 390.79389)), ((637.10413, 390.79389), (637.0208, 390.79389)), ((637.10413, 390.79389), (637.49996, 390.10828)), ((637.49996, 390.10828), (637.62496, 390.10828)), ((637.62496, 390.10828), (638.0208, 390.79389)), ((638.0208, 390.79389), (638.10413, 390.79389)), ((638.10413, 390.79389), (638.0208, 390.79389)), ((638.10413, 390.79389), (638.49996, 390.10828)), ((638.49996, 390.10828), (638.62496, 390.10828)), ((638.62496, 390.10828), (639.0208, 390.79389)), ((639.10413, 390.79389), (639.0208, 390.79389)), ((639.10413, 390.79389), (639.49996, 390.10828)), ((639.49996, 390.10828), (639.62496, 390.10828)), ((639.62496, 390.10828), (640.0208, 390.79389)), ((640.10413, 390.79389), (640.0208, 390.79389)), ((640.10413, 390.79389), (640.49996, 390.10828)), ((640.49996, 390.10828), (640.62496, 390.10828)), ((640.62496, 390.10828), (641.0208, 390.79389)), ((641.10413, 390.79389), (641.0208, 390.79389)), ((641.10413, 390.79389), (641.49996, 390.10828)), ((641.49996, 390.10828), (641.62496, 390.10828)), ((641.62496, 390.10828), (642.0208, 390.79389)), ((642.10413, 390.79389), (642.0208, 390.79389)), ((642.10413, 390.79389), (642.49996, 390.10828)), ((642.49996, 390.10828), (642.62496, 390.10828)), ((642.62496, 390.10828), (643.0208, 390.79389)), ((643.10413, 390.79389), (643.0208, 390.79389)), ((643.10413, 390.79389), (643.49996, 390.10828)), ((643.49996, 390.10828), (643.62496, 390.10828)), ((643.62496, 390.10828), (644.0208, 390.79389)), ((644.10413, 390.79389), (644.0208, 390.79389)), ((644.10413, 390.79389), (644.49996, 390.10828)), ((644.49996, 390.10828), (644.62496, 390.10828)), ((644.62496, 390.10828), (645.0208, 390.79389)), ((645.10413, 390.79389), (645.0208, 390.79389)), ((645.10413, 390.79389), (645.49996, 390.10828)), ((645.49996, 390.10828), (645.62496, 390.10828)), ((645.62496, 390.10828), (646.0208, 390.79389)), ((646.10413, 390.79389), (646.0208, 390.79389)), ((646.10413, 390.79389), (646.49996, 390.10828)), ((646.49996, 390.10828), (646.62496, 390.10828)), ((646.62496, 390.10828), (647.0208, 390.79389)), ((647.10413, 390.79389), (647.0208, 390.79389)), ((647.10413, 390.79389), (647.49996, 390.10828)), ((647.49996, 390.10828), (647.62496, 390.10828)), ((647.62496, 390.10828), (648.0208, 390.79389)), ((648.10413, 390.79389), (648.0208, 390.79389)), ((648.10413, 390.79389), (648.49996, 390.10828)), ((648.49996, 390.10828), (648.62496, 390.10828)), ((648.62496, 390.10828), (649.0208, 390.79389)), ((649.10413, 390.79389), (649.0208, 390.79389)), ((649.10413, 390.79389), (649.49996, 390.10828)), ((649.49996, 390.10828), (649.62496, 390.10828)), ((649.62496, 390.10828), (649.99996, 390.7578))]:
    msp.add_line(p, q)
for points in [[(0, 0), (841, 0), (841, 594), (0, 594)], [(18.5, 20), (822.5, 20), (822.5, 574), (18.5, 574)]]:
    msp.add_lwpolyline(points, close=True)
for centre, start, end in [((479.09996, 404.85003), 180, 270), ((600.09996, 404.62503), 180, 270), ((479.09996, 389.15003), 90, 180), ((600.09996, 389.37503), 90, 180)]:
    msp.add_arc(centre, 0.1, start, end)
at = {"layer": 'CENTERLINE'}
msp.add_line((146.49996, 397.00003), (651.49996, 397.00003), dxfattribs=at)
at = {"layer": 'HIDDEN'}
for p, q in [((199.17996, 400.91003), (649.99996, 400.91003)), ((199.17996, 400.81003), (649.99996, 400.81003)), ((199.17996, 393.19003), (649.99996, 393.19003)), ((199.17996, 393.09003), (649.99996, 393.09003))]:
    msp.add_line(p, q, dxfattribs=at)

# ---------------------------------------------------------------- texts
msp.add_text('Yugoslavian M77 7,62 x 51,0', height=6).set_placement((378, 517), align=Align.MIDDLE_CENTER)

doc.saveas('drawing.dxf')
